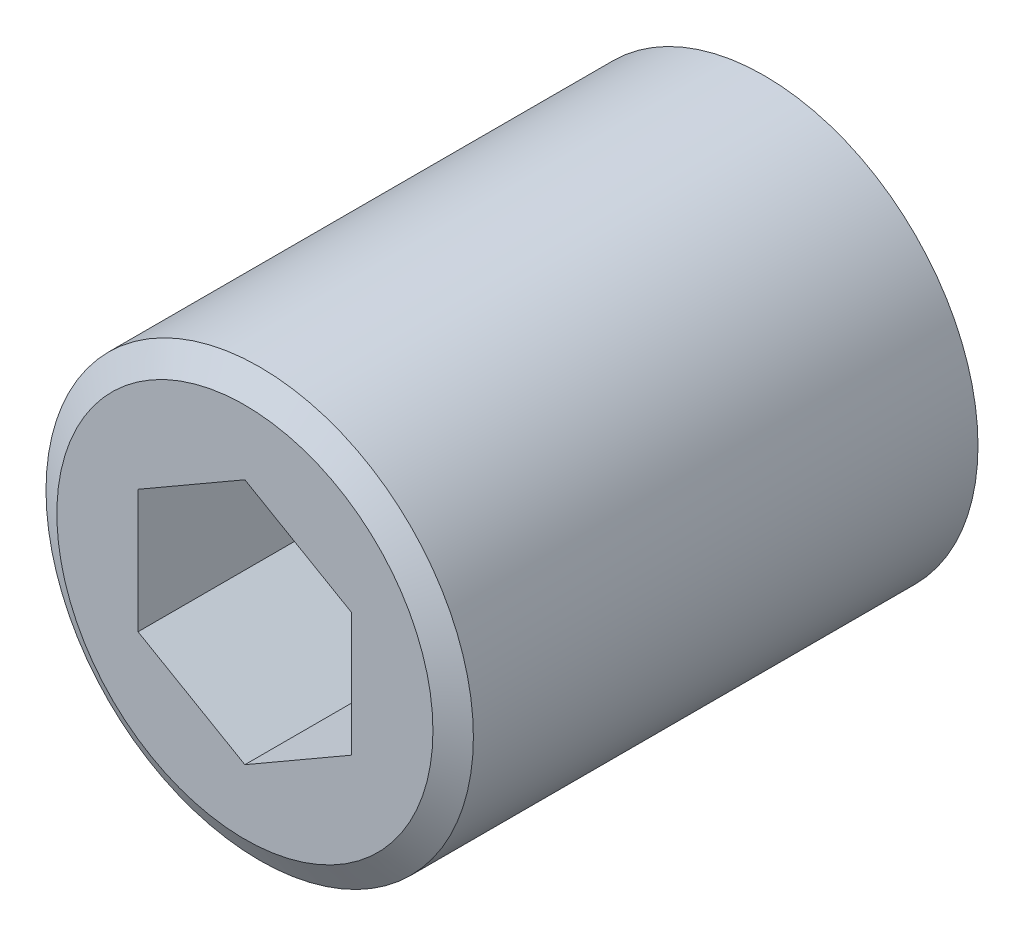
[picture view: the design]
ISO-10303-21;
HEADER;
FILE_DESCRIPTION(('STEP AP214'),'2;1');
FILE_NAME('part.step','',(''),(''),'','','');
FILE_SCHEMA(('AUTOMOTIVE_DESIGN { 1 0 10303 214 1 1 1 1 }'));
ENDSEC;
DATA;
#1=APPLICATION_CONTEXT('core data for automotive mechanical design processes');
#2=APPLICATION_PROTOCOL_DEFINITION('international standard','automotive_design',2000,#1);
#3=PRODUCT_CONTEXT('',#1,'mechanical');
#4=PRODUCT('Part','Part','',(#3));
#5=PRODUCT_RELATED_PRODUCT_CATEGORY('part','',(#4));
#6=PRODUCT_DEFINITION_FORMATION('','',#4);
#7=PRODUCT_DEFINITION_CONTEXT('part definition',#1,'design');
#8=PRODUCT_DEFINITION('design','',#6,#7);
#9=PRODUCT_DEFINITION_SHAPE('','',#8);
#10=(LENGTH_UNIT() NAMED_UNIT(*) SI_UNIT(.MILLI.,.METRE.));
#11=(NAMED_UNIT(*) PLANE_ANGLE_UNIT() SI_UNIT($,.RADIAN.));
#12=(NAMED_UNIT(*) SI_UNIT($,.STERADIAN.) SOLID_ANGLE_UNIT());
#13=UNCERTAINTY_MEASURE_WITH_UNIT(LENGTH_MEASURE(1.E-05),#10,'distance_accuracy_value','');
#14=(GEOMETRIC_REPRESENTATION_CONTEXT(3) GLOBAL_UNCERTAINTY_ASSIGNED_CONTEXT((#13)) GLOBAL_UNIT_ASSIGNED_CONTEXT((#10,
#11,#12)) REPRESENTATION_CONTEXT('',''));
#15=CARTESIAN_POINT('',(0.,0.,0.));
#16=DIRECTION('',(0.,0.,1.));
#17=DIRECTION('',(1.,0.,0.));
#18=AXIS2_PLACEMENT_3D('',#15,#16,#17);
#19=CARTESIAN_POINT('',(1.5,-6.35,0.));
#20=DIRECTION('',(-0.707106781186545,0.,0.70710678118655));
#21=DIRECTION('',(0.70710678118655,0.,0.707106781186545));
#22=AXIS2_PLACEMENT_3D('',#19,#20,#21);
#23=PLANE('',#22);
#24=CARTESIAN_POINT('',(0.,0.,-1.5));
#25=DIRECTION('',(-0.707106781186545,0.,0.70710678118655));
#26=DIRECTION('',(-0.70710678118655,0.,-0.707106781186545));
#27=AXIS2_PLACEMENT_3D('',#24,#25,#26);
#28=ELLIPSE('',#27,8.98025612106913,6.35);
#29=CARTESIAN_POINT('',(2.77,-5.71398284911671,1.27));
#30=VERTEX_POINT('',#29);
#31=CARTESIAN_POINT('',(3.,-5.59665078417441,1.5));
#32=VERTEX_POINT('',#31);
#33=EDGE_CURVE('E535',#30,#32,#28,.T.);
#34=ORIENTED_EDGE('',*,*,#33,.F.);
#35=CARTESIAN_POINT('',(0.,0.,-1.5));
#36=DIRECTION('',(-0.707106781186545,0.,0.70710678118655));
#37=DIRECTION('',(0.70710678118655,0.,0.707106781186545));
#38=AXIS2_PLACEMENT_3D('',#35,#36,#37);
#39=ELLIPSE('',#38,8.98025612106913,6.35);
#40=CARTESIAN_POINT('',(2.73216847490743,-5.73216847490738,1.2321684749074));
#41=VERTEX_POINT('',#40);
#42=EDGE_CURVE('E947',#41,#30,#39,.T.);
#43=ORIENTED_EDGE('',*,*,#42,.F.);
#44=DIRECTION('',(-0.577350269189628,0.577350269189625,-0.577350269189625));
#45=VECTOR('',#44,1.);
#46=CARTESIAN_POINT('',(2.11666666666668,-5.11666666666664,0.616666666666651));
#47=LINE('',#46,#45);
#48=CARTESIAN_POINT('',(1.49999999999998,-4.5,0.));
#49=VERTEX_POINT('',#48);
#50=EDGE_CURVE('E684',#41,#49,#47,.T.);
#51=ORIENTED_EDGE('',*,*,#50,.T.);
#52=DIRECTION('',(0.577350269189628,0.577350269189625,0.577350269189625));
#53=VECTOR('',#52,1.);
#54=CARTESIAN_POINT('',(0.883333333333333,-5.11666666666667,-0.616666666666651));
#55=LINE('',#54,#53);
#56=CARTESIAN_POINT('',(3.,-3.,1.5));
#57=VERTEX_POINT('',#56);
#58=EDGE_CURVE('E707',#49,#57,#55,.T.);
#59=ORIENTED_EDGE('',*,*,#58,.T.);
#60=DIRECTION('',(0.,1.,0.));
#61=VECTOR('',#60,1.);
#62=CARTESIAN_POINT('',(3.,-6.35,1.5));
#63=LINE('',#62,#61);
#64=EDGE_CURVE('E911',#32,#57,#63,.T.);
#65=ORIENTED_EDGE('',*,*,#64,.F.);
#66=EDGE_LOOP('',(#34,#43,#51,#59,#65));
#67=FACE_BOUND('',#66,.T.);
#68=ADVANCED_FACE('F15',(#67),#23,.F.);
#69=CARTESIAN_POINT('',(1.5,-6.35,0.));
#70=DIRECTION('',(0.707106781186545,0.,0.70710678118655));
#71=DIRECTION('',(0.70710678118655,0.,-0.707106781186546));
#72=AXIS2_PLACEMENT_3D('',#69,#70,#71);
#73=PLANE('',#72);
#74=CARTESIAN_POINT('',(0.,0.,1.5));
#75=DIRECTION('',(0.707106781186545,0.,0.70710678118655));
#76=DIRECTION('',(0.70710678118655,0.,-0.707106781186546));
#77=AXIS2_PLACEMENT_3D('',#74,#75,#76);
#78=ELLIPSE('',#77,8.98025612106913,6.35);
#79=CARTESIAN_POINT('',(0.,-6.35,1.5));
#80=VERTEX_POINT('',#79);
#81=CARTESIAN_POINT('',(0.229999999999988,-6.34583327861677,1.27));
#82=VERTEX_POINT('',#81);
#83=EDGE_CURVE('E579',#80,#82,#78,.T.);
#84=ORIENTED_EDGE('',*,*,#83,.F.);
#85=DIRECTION('',(0.,1.,0.));
#86=VECTOR('',#85,1.);
#87=CARTESIAN_POINT('',(0.,-6.35,1.5));
#88=LINE('',#87,#86);
#89=CARTESIAN_POINT('',(0.,-6.,1.5));
#90=VERTEX_POINT('',#89);
#91=EDGE_CURVE('E891',#80,#90,#88,.T.);
#92=ORIENTED_EDGE('',*,*,#91,.T.);
#93=DIRECTION('',(0.577350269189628,-0.577350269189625,-0.577350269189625));
#94=VECTOR('',#93,1.);
#95=CARTESIAN_POINT('',(1.11666666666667,-7.11666666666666,0.38333333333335));
#96=LINE('',#95,#94);
#97=CARTESIAN_POINT('',(0.340845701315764,-6.34084570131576,1.1591542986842));
#98=VERTEX_POINT('',#97);
#99=EDGE_CURVE('E671',#90,#98,#96,.T.);
#100=ORIENTED_EDGE('',*,*,#99,.T.);
#101=CARTESIAN_POINT('',(0.,0.,1.5));
#102=DIRECTION('',(0.707106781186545,0.,0.70710678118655));
#103=DIRECTION('',(-0.70710678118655,0.,0.707106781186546));
#104=AXIS2_PLACEMENT_3D('',#101,#102,#103);
#105=ELLIPSE('',#104,8.98025612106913,6.35);
#106=EDGE_CURVE('E946',#82,#98,#105,.T.);
#107=ORIENTED_EDGE('',*,*,#106,.F.);
#108=EDGE_LOOP('',(#84,#92,#100,#107));
#109=FACE_BOUND('',#108,.T.);
#110=ADVANCED_FACE('F1126',(#109),#73,.F.);
#111=CARTESIAN_POINT('',(0.,0.,1.5));
#112=DIRECTION('',(0.707106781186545,0.,0.70710678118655));
#113=DIRECTION('',(0.70710678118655,0.,-0.707106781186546));
#114=AXIS2_PLACEMENT_3D('',#111,#112,#113);
#115=ELLIPSE('',#114,8.98025612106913,6.35);
#116=CARTESIAN_POINT('',(0.229999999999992,6.34583327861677,1.27));
#117=VERTEX_POINT('',#116);
#118=CARTESIAN_POINT('',(0.,6.35,1.5));
#119=VERTEX_POINT('',#118);
#120=EDGE_CURVE('E575',#117,#119,#115,.T.);
#121=ORIENTED_EDGE('',*,*,#120,.F.);
#122=CARTESIAN_POINT('',(0.340845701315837,6.34084570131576,1.15915429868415));
#123=VERTEX_POINT('',#122);
#124=EDGE_CURVE('E391',#123,#117,#105,.T.);
#125=ORIENTED_EDGE('',*,*,#124,.F.);
#126=DIRECTION('',(-0.577350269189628,-0.577350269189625,0.577350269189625));
#127=VECTOR('',#126,1.);
#128=CARTESIAN_POINT('',(-3.11666666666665,2.88333333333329,4.6166666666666));
#129=LINE('',#128,#127);
#130=CARTESIAN_POINT('',(0.,6.,1.5));
#131=VERTEX_POINT('',#130);
#132=EDGE_CURVE('E407',#123,#131,#129,.T.);
#133=ORIENTED_EDGE('',*,*,#132,.T.);
#134=EDGE_CURVE('E897',#131,#119,#88,.T.);
#135=ORIENTED_EDGE('',*,*,#134,.T.);
#136=EDGE_LOOP('',(#121,#125,#133,#135));
#137=FACE_BOUND('',#136,.T.);
#138=ADVANCED_FACE('F1134',(#137),#73,.F.);
#139=CARTESIAN_POINT('',(0.,-6.35,1.5));
#140=DIRECTION('',(-0.70710678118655,0.,0.707106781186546));
#141=DIRECTION('',(0.707106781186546,0.,0.70710678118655));
#142=AXIS2_PLACEMENT_3D('',#139,#140,#141);
#143=PLANE('',#142);
#144=CARTESIAN_POINT('',(0.,0.,1.5));
#145=DIRECTION('',(-0.70710678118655,0.,0.707106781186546));
#146=DIRECTION('',(-0.707106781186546,0.,-0.70710678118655));
#147=AXIS2_PLACEMENT_3D('',#144,#145,#146);
#148=ELLIPSE('',#147,8.98025612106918,6.35);
#149=CARTESIAN_POINT('',(-0.229999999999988,-6.34583327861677,1.27));
#150=VERTEX_POINT('',#149);
#151=EDGE_CURVE('E528',#150,#80,#148,.T.);
#152=ORIENTED_EDGE('',*,*,#151,.F.);
#153=CARTESIAN_POINT('',(0.,0.,1.5));
#154=DIRECTION('',(-0.70710678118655,0.,0.707106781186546));
#155=DIRECTION('',(0.707106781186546,0.,0.70710678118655));
#156=AXIS2_PLACEMENT_3D('',#153,#154,#155);
#157=ELLIPSE('',#156,8.98025612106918,6.35);
#158=CARTESIAN_POINT('',(-0.34084570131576,-6.34084570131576,1.1591542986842));
#159=VERTEX_POINT('',#158);
#160=EDGE_CURVE('E939',#159,#150,#157,.T.);
#161=ORIENTED_EDGE('',*,*,#160,.F.);
#162=DIRECTION('',(0.577350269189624,0.577350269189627,0.577350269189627));
#163=VECTOR('',#162,1.);
#164=CARTESIAN_POINT('',(-0.116666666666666,-6.11666666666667,1.3833333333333));
#165=LINE('',#164,#163);
#166=EDGE_CURVE('E675',#159,#90,#165,.T.);
#167=ORIENTED_EDGE('',*,*,#166,.T.);
#168=ORIENTED_EDGE('',*,*,#91,.F.);
#169=EDGE_LOOP('',(#152,#161,#167,#168));
#170=FACE_BOUND('',#169,.T.);
#171=ADVANCED_FACE('F1395',(#170),#143,.F.);
#172=CARTESIAN_POINT('',(0.,0.,1.5));
#173=DIRECTION('',(-0.70710678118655,0.,0.707106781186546));
#174=DIRECTION('',(-0.707106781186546,0.,-0.70710678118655));
#175=AXIS2_PLACEMENT_3D('',#172,#173,#174);
#176=ELLIPSE('',#175,8.98025612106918,6.35);
#177=CARTESIAN_POINT('',(-0.229999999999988,6.34583327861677,1.27));
#178=VERTEX_POINT('',#177);
#179=EDGE_CURVE('E524',#119,#178,#176,.T.);
#180=ORIENTED_EDGE('',*,*,#179,.F.);
#181=ORIENTED_EDGE('',*,*,#134,.F.);
#182=DIRECTION('',(-0.577350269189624,0.577350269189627,-0.577350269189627));
#183=VECTOR('',#182,1.);
#184=CARTESIAN_POINT('',(4.11666666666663,1.88333333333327,5.61666666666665));
#185=LINE('',#184,#183);
#186=CARTESIAN_POINT('',(-0.340845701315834,6.34084570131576,1.15915429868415));
#187=VERTEX_POINT('',#186);
#188=EDGE_CURVE('E659',#131,#187,#185,.T.);
#189=ORIENTED_EDGE('',*,*,#188,.T.);
#190=EDGE_CURVE('E943',#178,#187,#157,.T.);
#191=ORIENTED_EDGE('',*,*,#190,.F.);
#192=EDGE_LOOP('',(#180,#181,#189,#191));
#193=FACE_BOUND('',#192,.T.);
#194=ADVANCED_FACE('F1392',(#193),#143,.F.);
#195=CARTESIAN_POINT('',(-1.5,-6.35,0.));
#196=DIRECTION('',(0.707106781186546,0.,0.707106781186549));
#197=DIRECTION('',(0.707106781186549,0.,-0.707106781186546));
#198=AXIS2_PLACEMENT_3D('',#195,#196,#197);
#199=PLANE('',#198);
#200=CARTESIAN_POINT('',(0.,0.,-1.5));
#201=DIRECTION('',(0.707106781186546,0.,0.707106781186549));
#202=DIRECTION('',(0.707106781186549,0.,-0.707106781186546));
#203=AXIS2_PLACEMENT_3D('',#200,#201,#202);
#204=ELLIPSE('',#203,8.98025612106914,6.35);
#205=CARTESIAN_POINT('',(-3.,-5.59665078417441,1.5));
#206=VERTEX_POINT('',#205);
#207=CARTESIAN_POINT('',(-2.77,-5.71398284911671,1.27));
#208=VERTEX_POINT('',#207);
#209=EDGE_CURVE('E31',#206,#208,#204,.T.);
#210=ORIENTED_EDGE('',*,*,#209,.F.);
#211=DIRECTION('',(0.,1.,0.));
#212=VECTOR('',#211,1.);
#213=CARTESIAN_POINT('',(-3.,-6.35,1.5));
#214=LINE('',#213,#212);
#215=CARTESIAN_POINT('',(-3.,-3.,1.5));
#216=VERTEX_POINT('',#215);
#217=EDGE_CURVE('E898',#206,#216,#214,.T.);
#218=ORIENTED_EDGE('',*,*,#217,.T.);
#219=DIRECTION('',(0.577350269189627,-0.577350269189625,-0.577350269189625));
#220=VECTOR('',#219,1.);
#221=CARTESIAN_POINT('',(-0.883333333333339,-5.11666666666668,-0.616666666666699));
#222=LINE('',#221,#220);
#223=CARTESIAN_POINT('',(-1.5,-4.49999999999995,0.));
#224=VERTEX_POINT('',#223);
#225=EDGE_CURVE('E723',#216,#224,#222,.T.);
#226=ORIENTED_EDGE('',*,*,#225,.T.);
#227=DIRECTION('',(-0.577350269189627,-0.577350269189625,0.577350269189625));
#228=VECTOR('',#227,1.);
#229=CARTESIAN_POINT('',(-2.11666666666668,-5.11666666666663,0.616666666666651));
#230=LINE('',#229,#228);
#231=CARTESIAN_POINT('',(-2.73216847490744,-5.73216847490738,1.2321684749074));
#232=VERTEX_POINT('',#231);
#233=EDGE_CURVE('E699',#224,#232,#230,.T.);
#234=ORIENTED_EDGE('',*,*,#233,.T.);
#235=CARTESIAN_POINT('',(0.,0.,-1.5));
#236=DIRECTION('',(0.707106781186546,0.,0.707106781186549));
#237=DIRECTION('',(-0.707106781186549,0.,0.707106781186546));
#238=AXIS2_PLACEMENT_3D('',#235,#236,#237);
#239=ELLIPSE('',#238,8.98025612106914,6.35);
#240=EDGE_CURVE('E938',#208,#232,#239,.T.);
#241=ORIENTED_EDGE('',*,*,#240,.F.);
#242=EDGE_LOOP('',(#210,#218,#226,#234,#241));
#243=FACE_BOUND('',#242,.T.);
#244=ADVANCED_FACE('F1714',(#243),#199,.F.);
#245=CARTESIAN_POINT('',(-3.,-6.35,1.5));
#246=DIRECTION('',(-0.707106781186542,0.,0.707106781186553));
#247=DIRECTION('',(0.707106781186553,0.,0.707106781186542));
#248=AXIS2_PLACEMENT_3D('',#245,#246,#247);
#249=PLANE('',#248);
#250=CARTESIAN_POINT('',(0.,0.,4.5));
#251=DIRECTION('',(-0.707106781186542,0.,0.707106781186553));
#252=DIRECTION('',(-0.707106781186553,0.,-0.707106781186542));
#253=AXIS2_PLACEMENT_3D('',#250,#251,#252);
#254=ELLIPSE('',#253,8.98025612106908,6.35);
#255=CARTESIAN_POINT('',(-3.23,-5.46713819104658,1.27));
#256=VERTEX_POINT('',#255);
#257=EDGE_CURVE('E569',#256,#206,#254,.T.);
#258=ORIENTED_EDGE('',*,*,#257,.F.);
#259=CARTESIAN_POINT('',(0.,0.,4.5));
#260=DIRECTION('',(-0.707106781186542,0.,0.707106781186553));
#261=DIRECTION('',(0.707106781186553,0.,0.707106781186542));
#262=AXIS2_PLACEMENT_3D('',#259,#260,#261);
#263=ELLIPSE('',#262,8.98025612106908,6.35);
#264=CARTESIAN_POINT('',(-4.49012806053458,-4.49012806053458,0.00987193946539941));
#265=VERTEX_POINT('',#264);
#266=EDGE_CURVE('E929',#265,#256,#263,.T.);
#267=ORIENTED_EDGE('',*,*,#266,.F.);
#268=DIRECTION('',(0.577350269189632,0.577350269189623,0.577350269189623));
#269=VECTOR('',#268,1.);
#270=CARTESIAN_POINT('',(-4.11666666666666,-4.11666666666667,0.38333333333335));
#271=LINE('',#270,#269);
#272=EDGE_CURVE('E726',#265,#216,#271,.T.);
#273=ORIENTED_EDGE('',*,*,#272,.T.);
#274=ORIENTED_EDGE('',*,*,#217,.F.);
#275=EDGE_LOOP('',(#258,#267,#273,#274));
#276=FACE_BOUND('',#275,.T.);
#277=ADVANCED_FACE('F1706',(#276),#249,.F.);
#278=CARTESIAN_POINT('',(-4.5,-6.35,0.));
#279=DIRECTION('',(0.707106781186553,0.,0.707106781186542));
#280=DIRECTION('',(0.707106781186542,0.,-0.707106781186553));
#281=AXIS2_PLACEMENT_3D('',#278,#279,#280);
#282=PLANE('',#281);
#283=CARTESIAN_POINT('',(0.,0.,-4.5));
#284=DIRECTION('',(0.707106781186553,0.,0.707106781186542));
#285=DIRECTION('',(0.707106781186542,0.,-0.707106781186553));
#286=AXIS2_PLACEMENT_3D('',#283,#284,#285);
#287=ELLIPSE('',#286,8.98025612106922,6.35);
#288=CARTESIAN_POINT('',(-5.77,2.65133928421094,1.27));
#289=VERTEX_POINT('',#288);
#290=CARTESIAN_POINT('',(-6.,2.07906228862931,1.5));
#291=VERTEX_POINT('',#290);
#292=EDGE_CURVE('E565',#289,#291,#287,.T.);
#293=ORIENTED_EDGE('',*,*,#292,.F.);
#294=CARTESIAN_POINT('',(0.,0.,-4.5));
#295=DIRECTION('',(0.707106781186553,0.,0.707106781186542));
#296=DIRECTION('',(-0.707106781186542,0.,0.707106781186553));
#297=AXIS2_PLACEMENT_3D('',#294,#295,#296);
#298=ELLIPSE('',#297,8.98025612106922,6.35);
#299=CARTESIAN_POINT('',(-5.73216847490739,2.73216847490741,1.2321684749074));
#300=VERTEX_POINT('',#299);
#301=EDGE_CURVE('E924',#300,#289,#298,.T.);
#302=ORIENTED_EDGE('',*,*,#301,.F.);
#303=DIRECTION('',(0.57735026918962,-0.577350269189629,-0.577350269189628));
#304=VECTOR('',#303,1.);
#305=CARTESIAN_POINT('',(-1.88333333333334,-1.1166666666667,-2.6166666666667));
#306=LINE('',#305,#304);
#307=CARTESIAN_POINT('',(-4.5,1.49999999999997,0.));
#308=VERTEX_POINT('',#307);
#309=EDGE_CURVE('E883',#300,#308,#306,.T.);
#310=ORIENTED_EDGE('',*,*,#309,.T.);
#311=DIRECTION('',(-0.57735026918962,-0.577350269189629,0.577350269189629));
#312=VECTOR('',#311,1.);
#313=CARTESIAN_POINT('',(-7.11666666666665,-1.11666666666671,2.6166666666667));
#314=LINE('',#313,#312);
#315=CARTESIAN_POINT('',(-6.,0.,1.5));
#316=VERTEX_POINT('',#315);
#317=EDGE_CURVE('E844',#308,#316,#314,.T.);
#318=ORIENTED_EDGE('',*,*,#317,.T.);
#319=DIRECTION('',(0.,1.,0.));
#320=VECTOR('',#319,1.);
#321=CARTESIAN_POINT('',(-6.,-6.35,1.5));
#322=LINE('',#321,#320);
#323=EDGE_CURVE('E906',#316,#291,#322,.T.);
#324=ORIENTED_EDGE('',*,*,#323,.T.);
#325=EDGE_LOOP('',(#293,#302,#310,#318,#324));
#326=FACE_BOUND('',#325,.T.);
#327=ADVANCED_FACE('F2388',(#326),#282,.F.);
#328=CARTESIAN_POINT('',(0.,0.,-4.5));
#329=DIRECTION('',(0.707106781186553,0.,0.707106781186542));
#330=DIRECTION('',(0.707106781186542,0.,-0.707106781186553));
#331=AXIS2_PLACEMENT_3D('',#328,#329,#330);
#332=ELLIPSE('',#331,8.98025612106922,6.35);
#333=CARTESIAN_POINT('',(-6.,-2.07906228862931,1.5));
#334=VERTEX_POINT('',#333);
#335=CARTESIAN_POINT('',(-5.77,-2.65133928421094,1.27));
#336=VERTEX_POINT('',#335);
#337=EDGE_CURVE('E559',#334,#336,#332,.T.);
#338=ORIENTED_EDGE('',*,*,#337,.F.);
#339=EDGE_CURVE('E903',#334,#316,#322,.T.);
#340=ORIENTED_EDGE('',*,*,#339,.T.);
#341=DIRECTION('',(0.57735026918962,-0.577350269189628,-0.577350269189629));
#342=VECTOR('',#341,1.);
#343=CARTESIAN_POINT('',(-2.88333333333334,-3.11666666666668,-1.6166666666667));
#344=LINE('',#343,#342);
#345=CARTESIAN_POINT('',(-4.5,-1.5,0.));
#346=VERTEX_POINT('',#345);
#347=EDGE_CURVE('E801',#316,#346,#344,.T.);
#348=ORIENTED_EDGE('',*,*,#347,.T.);
#349=DIRECTION('',(-0.57735026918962,-0.577350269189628,0.577350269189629));
#350=VECTOR('',#349,1.);
#351=CARTESIAN_POINT('',(-6.11666666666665,-3.11666666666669,1.61666666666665));
#352=LINE('',#351,#350);
#353=CARTESIAN_POINT('',(-5.73216847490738,-2.73216847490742,1.2321684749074));
#354=VERTEX_POINT('',#353);
#355=EDGE_CURVE('E762',#346,#354,#352,.T.);
#356=ORIENTED_EDGE('',*,*,#355,.T.);
#357=EDGE_CURVE('E928',#336,#354,#298,.T.);
#358=ORIENTED_EDGE('',*,*,#357,.F.);
#359=EDGE_LOOP('',(#338,#340,#348,#356,#358));
#360=FACE_BOUND('',#359,.T.);
#361=ADVANCED_FACE('F2036',(#360),#282,.F.);
#362=CARTESIAN_POINT('',(-6.,-6.35,1.5));
#363=DIRECTION('',(-0.707106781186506,0.,0.70710678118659));
#364=DIRECTION('',(0.70710678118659,0.,0.707106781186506));
#365=AXIS2_PLACEMENT_3D('',#362,#363,#364);
#366=PLANE('',#365);
#367=CARTESIAN_POINT('',(0.,0.,7.4999999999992));
#368=DIRECTION('',(-0.707106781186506,0.,0.70710678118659));
#369=DIRECTION('',(-0.70710678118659,0.,-0.707106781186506));
#370=AXIS2_PLACEMENT_3D('',#367,#368,#369);
#371=ELLIPSE('',#370,8.98025612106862,6.35);
#372=CARTESIAN_POINT('',(-6.23,1.22865780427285,1.27));
#373=VERTEX_POINT('',#372);
#374=EDGE_CURVE('E39',#291,#373,#371,.T.);
#375=ORIENTED_EDGE('',*,*,#374,.F.);
#376=ORIENTED_EDGE('',*,*,#323,.F.);
#377=DIRECTION('',(-0.577350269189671,0.577350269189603,-0.577350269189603));
#378=VECTOR('',#377,1.);
#379=CARTESIAN_POINT('',(-3.8833333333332,-2.11666666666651,3.61666666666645));
#380=LINE('',#379,#378);
#381=CARTESIAN_POINT('',(-6.34084570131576,0.340845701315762,1.1591542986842));
#382=VERTEX_POINT('',#381);
#383=EDGE_CURVE('E848',#316,#382,#380,.T.);
#384=ORIENTED_EDGE('',*,*,#383,.T.);
#385=CARTESIAN_POINT('',(0.,0.,7.4999999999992));
#386=DIRECTION('',(-0.707106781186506,0.,0.70710678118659));
#387=DIRECTION('',(0.70710678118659,0.,0.707106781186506));
#388=AXIS2_PLACEMENT_3D('',#385,#386,#387);
#389=ELLIPSE('',#388,8.98025612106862,6.35);
#390=EDGE_CURVE('E1031',#373,#382,#389,.T.);
#391=ORIENTED_EDGE('',*,*,#390,.F.);
#392=EDGE_LOOP('',(#375,#376,#384,#391));
#393=FACE_BOUND('',#392,.T.);
#394=ADVANCED_FACE('F2372',(#393),#366,.F.);
#395=CARTESIAN_POINT('',(0.,0.,7.4999999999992));
#396=DIRECTION('',(-0.707106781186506,0.,0.70710678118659));
#397=DIRECTION('',(-0.70710678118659,0.,-0.707106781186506));
#398=AXIS2_PLACEMENT_3D('',#395,#396,#397);
#399=ELLIPSE('',#398,8.98025612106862,6.35);
#400=CARTESIAN_POINT('',(-6.23,-1.22865780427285,1.27));
#401=VERTEX_POINT('',#400);
#402=EDGE_CURVE('E555',#401,#334,#399,.T.);
#403=ORIENTED_EDGE('',*,*,#402,.F.);
#404=CARTESIAN_POINT('',(-6.34084570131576,-0.340845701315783,1.1591542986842));
#405=VERTEX_POINT('',#404);
#406=EDGE_CURVE('E1029',#405,#401,#389,.T.);
#407=ORIENTED_EDGE('',*,*,#406,.F.);
#408=DIRECTION('',(0.577350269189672,0.577350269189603,0.577350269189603));
#409=VECTOR('',#408,1.);
#410=CARTESIAN_POINT('',(-8.1166666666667,-2.11666666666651,-0.616666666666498));
#411=LINE('',#410,#409);
#412=EDGE_CURVE('E804',#405,#316,#411,.T.);
#413=ORIENTED_EDGE('',*,*,#412,.T.);
#414=ORIENTED_EDGE('',*,*,#339,.F.);
#415=EDGE_LOOP('',(#403,#407,#413,#414));
#416=FACE_BOUND('',#415,.T.);
#417=ADVANCED_FACE('F2364',(#416),#366,.F.);
#418=CARTESIAN_POINT('',(6.,-6.35,1.5));
#419=DIRECTION('',(0.707106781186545,0.,0.70710678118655));
#420=DIRECTION('',(0.70710678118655,0.,-0.707106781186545));
#421=AXIS2_PLACEMENT_3D('',#418,#419,#420);
#422=PLANE('',#421);
#423=CARTESIAN_POINT('',(0.,0.,7.5));
#424=DIRECTION('',(0.707106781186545,0.,0.70710678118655));
#425=DIRECTION('',(0.70710678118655,0.,-0.707106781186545));
#426=AXIS2_PLACEMENT_3D('',#423,#424,#425);
#427=ELLIPSE('',#426,8.98025612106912,6.35);
#428=CARTESIAN_POINT('',(6.23,1.22865780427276,1.27));
#429=VERTEX_POINT('',#428);
#430=CARTESIAN_POINT('',(6.,2.07906228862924,1.5));
#431=VERTEX_POINT('',#430);
#432=EDGE_CURVE('E551',#429,#431,#427,.T.);
#433=ORIENTED_EDGE('',*,*,#432,.F.);
#434=CARTESIAN_POINT('',(0.,0.,7.5));
#435=DIRECTION('',(0.707106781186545,0.,0.70710678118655));
#436=DIRECTION('',(-0.70710678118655,0.,0.707106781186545));
#437=AXIS2_PLACEMENT_3D('',#434,#435,#436);
#438=ELLIPSE('',#437,8.98025612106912,6.35);
#439=CARTESIAN_POINT('',(6.34084570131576,0.340845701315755,1.1591542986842));
#440=VERTEX_POINT('',#439);
#441=EDGE_CURVE('E1030',#440,#429,#438,.T.);
#442=ORIENTED_EDGE('',*,*,#441,.F.);
#443=DIRECTION('',(-0.577350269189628,-0.577350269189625,0.577350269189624));
#444=VECTOR('',#443,1.);
#445=CARTESIAN_POINT('',(3.88333333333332,-2.11666666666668,3.61666666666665));
#446=LINE('',#445,#444);
#447=CARTESIAN_POINT('',(6.,0.,1.5));
#448=VERTEX_POINT('',#447);
#449=EDGE_CURVE('E816',#440,#448,#446,.T.);
#450=ORIENTED_EDGE('',*,*,#449,.T.);
#451=DIRECTION('',(0.,1.,0.));
#452=VECTOR('',#451,1.);
#453=CARTESIAN_POINT('',(6.,-6.35,1.5));
#454=LINE('',#453,#452);
#455=EDGE_CURVE('E910',#448,#431,#454,.T.);
#456=ORIENTED_EDGE('',*,*,#455,.T.);
#457=EDGE_LOOP('',(#433,#442,#450,#456));
#458=FACE_BOUND('',#457,.T.);
#459=ADVANCED_FACE('F2062',(#458),#422,.F.);
#460=CARTESIAN_POINT('',(0.,0.,7.5));
#461=DIRECTION('',(0.707106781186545,0.,0.70710678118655));
#462=DIRECTION('',(0.70710678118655,0.,-0.707106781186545));
#463=AXIS2_PLACEMENT_3D('',#460,#461,#462);
#464=ELLIPSE('',#463,8.98025612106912,6.35);
#465=CARTESIAN_POINT('',(6.,-2.07906228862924,1.5));
#466=VERTEX_POINT('',#465);
#467=CARTESIAN_POINT('',(6.23,-1.22865780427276,1.27));
#468=VERTEX_POINT('',#467);
#469=EDGE_CURVE('E543',#466,#468,#464,.T.);
#470=ORIENTED_EDGE('',*,*,#469,.F.);
#471=EDGE_CURVE('E907',#466,#448,#454,.T.);
#472=ORIENTED_EDGE('',*,*,#471,.T.);
#473=DIRECTION('',(0.577350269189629,-0.577350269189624,-0.577350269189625));
#474=VECTOR('',#473,1.);
#475=CARTESIAN_POINT('',(8.11666666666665,-2.11666666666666,-0.616666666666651));
#476=LINE('',#475,#474);
#477=CARTESIAN_POINT('',(6.34084570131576,-0.340845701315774,1.1591542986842));
#478=VERTEX_POINT('',#477);
#479=EDGE_CURVE('E774',#448,#478,#476,.T.);
#480=ORIENTED_EDGE('',*,*,#479,.T.);
#481=EDGE_CURVE('E1025',#468,#478,#438,.T.);
#482=ORIENTED_EDGE('',*,*,#481,.F.);
#483=EDGE_LOOP('',(#470,#472,#480,#482));
#484=FACE_BOUND('',#483,.T.);
#485=ADVANCED_FACE('F2076',(#484),#422,.F.);
#486=CARTESIAN_POINT('',(4.5,-6.35,0.));
#487=DIRECTION('',(-0.70710678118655,0.,0.707106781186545));
#488=DIRECTION('',(0.707106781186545,0.,0.70710678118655));
#489=AXIS2_PLACEMENT_3D('',#486,#487,#488);
#490=PLANE('',#489);
#491=CARTESIAN_POINT('',(0.,0.,-4.5));
#492=DIRECTION('',(-0.70710678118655,0.,0.707106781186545));
#493=DIRECTION('',(-0.707106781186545,0.,-0.70710678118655));
#494=AXIS2_PLACEMENT_3D('',#491,#492,#493);
#495=ELLIPSE('',#494,8.98025612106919,6.35);
#496=CARTESIAN_POINT('',(5.77,2.65133928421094,1.27));
#497=VERTEX_POINT('',#496);
#498=EDGE_CURVE('E547',#431,#497,#495,.T.);
#499=ORIENTED_EDGE('',*,*,#498,.F.);
#500=ORIENTED_EDGE('',*,*,#455,.F.);
#501=DIRECTION('',(-0.577350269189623,0.577350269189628,-0.577350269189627));
#502=VECTOR('',#501,1.);
#503=CARTESIAN_POINT('',(7.11666666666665,-1.1166666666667,2.61666666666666));
#504=LINE('',#503,#502);
#505=CARTESIAN_POINT('',(4.5,1.49999999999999,0.));
#506=VERTEX_POINT('',#505);
#507=EDGE_CURVE('E812',#448,#506,#504,.T.);
#508=ORIENTED_EDGE('',*,*,#507,.T.);
#509=DIRECTION('',(0.577350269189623,0.577350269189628,0.577350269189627));
#510=VECTOR('',#509,1.);
#511=CARTESIAN_POINT('',(1.88333333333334,-1.11666666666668,-2.6166666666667));
#512=LINE('',#511,#510);
#513=CARTESIAN_POINT('',(5.73216847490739,2.73216847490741,1.2321684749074));
#514=VERTEX_POINT('',#513);
#515=EDGE_CURVE('E856',#506,#514,#512,.T.);
#516=ORIENTED_EDGE('',*,*,#515,.T.);
#517=CARTESIAN_POINT('',(0.,0.,-4.5));
#518=DIRECTION('',(-0.70710678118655,0.,0.707106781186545));
#519=DIRECTION('',(0.707106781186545,0.,0.70710678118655));
#520=AXIS2_PLACEMENT_3D('',#517,#518,#519);
#521=ELLIPSE('',#520,8.98025612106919,6.35);
#522=EDGE_CURVE('E923',#497,#514,#521,.T.);
#523=ORIENTED_EDGE('',*,*,#522,.F.);
#524=EDGE_LOOP('',(#499,#500,#508,#516,#523));
#525=FACE_BOUND('',#524,.T.);
#526=ADVANCED_FACE('F2059',(#525),#490,.F.);
#527=CARTESIAN_POINT('',(0.,0.,-4.5));
#528=DIRECTION('',(-0.70710678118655,0.,0.707106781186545));
#529=DIRECTION('',(-0.707106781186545,0.,-0.70710678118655));
#530=AXIS2_PLACEMENT_3D('',#527,#528,#529);
#531=ELLIPSE('',#530,8.98025612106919,6.35);
#532=CARTESIAN_POINT('',(5.77,-2.65133928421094,1.27));
#533=VERTEX_POINT('',#532);
#534=EDGE_CURVE('E539',#533,#466,#531,.T.);
#535=ORIENTED_EDGE('',*,*,#534,.F.);
#536=CARTESIAN_POINT('',(5.73216847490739,-2.73216847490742,1.2321684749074));
#537=VERTEX_POINT('',#536);
#538=EDGE_CURVE('E919',#537,#533,#521,.T.);
#539=ORIENTED_EDGE('',*,*,#538,.F.);
#540=DIRECTION('',(-0.577350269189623,0.577350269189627,-0.577350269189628));
#541=VECTOR('',#540,1.);
#542=CARTESIAN_POINT('',(6.11666666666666,-3.11666666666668,1.61666666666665));
#543=LINE('',#542,#541);
#544=CARTESIAN_POINT('',(4.5,-1.5,0.));
#545=VERTEX_POINT('',#544);
#546=EDGE_CURVE('E734',#537,#545,#543,.T.);
#547=ORIENTED_EDGE('',*,*,#546,.T.);
#548=DIRECTION('',(0.577350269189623,0.577350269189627,0.577350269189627));
#549=VECTOR('',#548,1.);
#550=CARTESIAN_POINT('',(2.88333333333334,-3.11666666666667,-1.6166666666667));
#551=LINE('',#550,#549);
#552=EDGE_CURVE('E770',#545,#448,#551,.T.);
#553=ORIENTED_EDGE('',*,*,#552,.T.);
#554=ORIENTED_EDGE('',*,*,#471,.F.);
#555=EDGE_LOOP('',(#535,#539,#547,#553,#554));
#556=FACE_BOUND('',#555,.T.);
#557=ADVANCED_FACE('F1189',(#556),#490,.F.);
#558=CARTESIAN_POINT('',(3.,-6.35,1.5));
#559=DIRECTION('',(0.707106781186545,0.,0.70710678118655));
#560=DIRECTION('',(0.70710678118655,0.,-0.707106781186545));
#561=AXIS2_PLACEMENT_3D('',#558,#559,#560);
#562=PLANE('',#561);
#563=CARTESIAN_POINT('',(0.,0.,4.5));
#564=DIRECTION('',(0.707106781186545,0.,0.70710678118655));
#565=DIRECTION('',(0.70710678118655,0.,-0.707106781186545));
#566=AXIS2_PLACEMENT_3D('',#563,#564,#565);
#567=ELLIPSE('',#566,8.98025612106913,6.35);
#568=CARTESIAN_POINT('',(3.23,-5.46713819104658,1.27));
#569=VERTEX_POINT('',#568);
#570=EDGE_CURVE('E531',#32,#569,#567,.T.);
#571=ORIENTED_EDGE('',*,*,#570,.F.);
#572=ORIENTED_EDGE('',*,*,#64,.T.);
#573=DIRECTION('',(0.577350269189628,-0.577350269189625,-0.577350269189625));
#574=VECTOR('',#573,1.);
#575=CARTESIAN_POINT('',(4.11666666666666,-4.11666666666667,0.38333333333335));
#576=LINE('',#575,#574);
#577=CARTESIAN_POINT('',(4.49012806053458,-4.49012806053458,0.00987193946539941));
#578=VERTEX_POINT('',#577);
#579=EDGE_CURVE('E1055',#57,#578,#576,.T.);
#580=ORIENTED_EDGE('',*,*,#579,.T.);
#581=CARTESIAN_POINT('',(0.,0.,4.5));
#582=DIRECTION('',(0.707106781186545,0.,0.70710678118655));
#583=DIRECTION('',(-0.70710678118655,0.,0.707106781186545));
#584=AXIS2_PLACEMENT_3D('',#581,#582,#583);
#585=ELLIPSE('',#584,8.98025612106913,6.35);
#586=EDGE_CURVE('E918',#569,#578,#585,.T.);
#587=ORIENTED_EDGE('',*,*,#586,.F.);
#588=EDGE_LOOP('',(#571,#572,#580,#587));
#589=FACE_BOUND('',#588,.T.);
#590=ADVANCED_FACE('F1142',(#589),#562,.F.);
#591=CARTESIAN_POINT('',(0.,0.,-1.5));
#592=DIRECTION('',(-0.707106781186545,0.,0.70710678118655));
#593=DIRECTION('',(-0.70710678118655,0.,-0.707106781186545));
#594=AXIS2_PLACEMENT_3D('',#591,#592,#593);
#595=ELLIPSE('',#594,8.98025612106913,6.35);
#596=CARTESIAN_POINT('',(3.,5.59665078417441,1.5));
#597=VERTEX_POINT('',#596);
#598=CARTESIAN_POINT('',(2.77,5.71398284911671,1.27));
#599=VERTEX_POINT('',#598);
#600=EDGE_CURVE('E512',#597,#599,#595,.T.);
#601=ORIENTED_EDGE('',*,*,#600,.F.);
#602=CARTESIAN_POINT('',(3.,3.,1.5));
#603=VERTEX_POINT('',#602);
#604=EDGE_CURVE('E890',#603,#597,#63,.T.);
#605=ORIENTED_EDGE('',*,*,#604,.F.);
#606=DIRECTION('',(-0.577350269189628,0.577350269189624,-0.577350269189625));
#607=VECTOR('',#606,1.);
#608=CARTESIAN_POINT('',(5.11666666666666,0.883333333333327,3.61666666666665));
#609=LINE('',#608,#607);
#610=CARTESIAN_POINT('',(1.50000000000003,4.5,0.));
#611=VERTEX_POINT('',#610);
#612=EDGE_CURVE('E587',#603,#611,#609,.T.);
#613=ORIENTED_EDGE('',*,*,#612,.T.);
#614=DIRECTION('',(0.577350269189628,0.577350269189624,0.577350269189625));
#615=VECTOR('',#614,1.);
#616=CARTESIAN_POINT('',(-2.11666666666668,0.883333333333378,-3.61666666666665));
#617=LINE('',#616,#615);
#618=CARTESIAN_POINT('',(2.73216847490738,5.73216847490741,1.23216847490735));
#619=VERTEX_POINT('',#618);
#620=EDGE_CURVE('E636',#611,#619,#617,.T.);
#621=ORIENTED_EDGE('',*,*,#620,.T.);
#622=EDGE_CURVE('E951',#599,#619,#39,.T.);
#623=ORIENTED_EDGE('',*,*,#622,.F.);
#624=EDGE_LOOP('',(#601,#605,#613,#621,#623));
#625=FACE_BOUND('',#624,.T.);
#626=ADVANCED_FACE('F1129',(#625),#23,.F.);
#627=CARTESIAN_POINT('',(0.,0.,-1.5));
#628=DIRECTION('',(0.707106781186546,0.,0.707106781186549));
#629=DIRECTION('',(0.707106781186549,0.,-0.707106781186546));
#630=AXIS2_PLACEMENT_3D('',#627,#628,#629);
#631=ELLIPSE('',#630,8.98025612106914,6.35);
#632=CARTESIAN_POINT('',(-2.77,5.71398284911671,1.27));
#633=VERTEX_POINT('',#632);
#634=CARTESIAN_POINT('',(-3.,5.59665078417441,1.5));
#635=VERTEX_POINT('',#634);
#636=EDGE_CURVE('E520',#633,#635,#631,.T.);
#637=ORIENTED_EDGE('',*,*,#636,.F.);
#638=CARTESIAN_POINT('',(-2.73216847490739,5.7321684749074,1.23216847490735));
#639=VERTEX_POINT('',#638);
#640=EDGE_CURVE('E934',#639,#633,#239,.T.);
#641=ORIENTED_EDGE('',*,*,#640,.F.);
#642=DIRECTION('',(0.577350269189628,-0.577350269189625,-0.577350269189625));
#643=VECTOR('',#642,1.);
#644=CARTESIAN_POINT('',(2.11666666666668,0.883333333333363,-3.6166666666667));
#645=LINE('',#644,#643);
#646=CARTESIAN_POINT('',(-1.5,4.5,0.));
#647=VERTEX_POINT('',#646);
#648=EDGE_CURVE('E651',#639,#647,#645,.T.);
#649=ORIENTED_EDGE('',*,*,#648,.T.);
#650=DIRECTION('',(-0.577350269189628,-0.577350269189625,0.577350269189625));
#651=VECTOR('',#650,1.);
#652=CARTESIAN_POINT('',(-5.11666666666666,0.883333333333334,3.61666666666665));
#653=LINE('',#652,#651);
#654=CARTESIAN_POINT('',(-3.,3.,1.5));
#655=VERTEX_POINT('',#654);
#656=EDGE_CURVE('E623',#647,#655,#653,.T.);
#657=ORIENTED_EDGE('',*,*,#656,.T.);
#658=EDGE_CURVE('E902',#655,#635,#214,.T.);
#659=ORIENTED_EDGE('',*,*,#658,.T.);
#660=EDGE_LOOP('',(#637,#641,#649,#657,#659));
#661=FACE_BOUND('',#660,.T.);
#662=ADVANCED_FACE('F1141',(#661),#199,.F.);
#663=CARTESIAN_POINT('',(0.,0.,4.5));
#664=DIRECTION('',(-0.707106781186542,0.,0.707106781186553));
#665=DIRECTION('',(-0.707106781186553,0.,-0.707106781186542));
#666=AXIS2_PLACEMENT_3D('',#663,#664,#665);
#667=ELLIPSE('',#666,8.98025612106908,6.35);
#668=CARTESIAN_POINT('',(-3.23,5.46713819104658,1.27));
#669=VERTEX_POINT('',#668);
#670=EDGE_CURVE('E516',#635,#669,#667,.T.);
#671=ORIENTED_EDGE('',*,*,#670,.F.);
#672=ORIENTED_EDGE('',*,*,#658,.F.);
#673=DIRECTION('',(-0.577350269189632,0.577350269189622,-0.577350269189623));
#674=VECTOR('',#673,1.);
#675=CARTESIAN_POINT('',(0.116666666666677,-0.116666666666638,4.6166666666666));
#676=LINE('',#675,#674);
#677=CARTESIAN_POINT('',(-4.4901280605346,4.49012806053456,0.00987193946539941));
#678=VERTEX_POINT('',#677);
#679=EDGE_CURVE('E627',#655,#678,#676,.T.);
#680=ORIENTED_EDGE('',*,*,#679,.T.);
#681=EDGE_CURVE('E933',#669,#678,#263,.T.);
#682=ORIENTED_EDGE('',*,*,#681,.F.);
#683=EDGE_LOOP('',(#671,#672,#680,#682));
#684=FACE_BOUND('',#683,.T.);
#685=ADVANCED_FACE('F1524',(#684),#249,.F.);
#686=CARTESIAN_POINT('',(0.,0.,4.5));
#687=DIRECTION('',(0.707106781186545,0.,0.70710678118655));
#688=DIRECTION('',(0.70710678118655,0.,-0.707106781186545));
#689=AXIS2_PLACEMENT_3D('',#686,#687,#688);
#690=ELLIPSE('',#689,8.98025612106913,6.35);
#691=CARTESIAN_POINT('',(3.23,5.46713819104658,1.27));
#692=VERTEX_POINT('',#691);
#693=EDGE_CURVE('E508',#692,#597,#690,.T.);
#694=ORIENTED_EDGE('',*,*,#693,.F.);
#695=CARTESIAN_POINT('',(4.4901280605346,4.49012806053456,0.00987193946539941));
#696=VERTEX_POINT('',#695);
#697=EDGE_CURVE('E895',#696,#692,#585,.T.);
#698=ORIENTED_EDGE('',*,*,#697,.F.);
#699=DIRECTION('',(-0.577350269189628,-0.577350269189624,0.577350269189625));
#700=VECTOR('',#699,1.);
#701=CARTESIAN_POINT('',(-0.116666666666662,-0.116666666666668,4.61666666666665));
#702=LINE('',#701,#700);
#703=EDGE_CURVE('E1035',#696,#603,#702,.T.);
#704=ORIENTED_EDGE('',*,*,#703,.T.);
#705=ORIENTED_EDGE('',*,*,#604,.T.);
#706=EDGE_LOOP('',(#694,#698,#704,#705));
#707=FACE_BOUND('',#706,.T.);
#708=ADVANCED_FACE('F1171',(#707),#562,.F.);
#709=CARTESIAN_POINT('',(6.35,3.,1.5));
#710=DIRECTION('',(0.,0.707106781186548,0.707106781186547));
#711=DIRECTION('',(0.,0.707106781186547,-0.707106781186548));
#712=AXIS2_PLACEMENT_3D('',#709,#710,#711);
#713=PLANE('',#712);
#714=CARTESIAN_POINT('',(0.,0.,4.5));
#715=DIRECTION('',(0.,0.707106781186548,0.707106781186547));
#716=DIRECTION('',(0.,0.707106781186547,-0.707106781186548));
#717=AXIS2_PLACEMENT_3D('',#714,#715,#716);
#718=ELLIPSE('',#717,8.98025612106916,6.35);
#719=CARTESIAN_POINT('',(5.59665078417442,3.,1.5));
#720=VERTEX_POINT('',#719);
#721=CARTESIAN_POINT('',(5.4671381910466,3.22999999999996,1.27));
#722=VERTEX_POINT('',#721);
#723=EDGE_CURVE('E504',#720,#722,#718,.T.);
#724=ORIENTED_EDGE('',*,*,#723,.F.);
#725=DIRECTION('',(-1.,0.,0.));
#726=VECTOR('',#725,1.);
#727=CARTESIAN_POINT('',(6.35,3.,1.5));
#728=LINE('',#727,#726);
#729=EDGE_CURVE('E604',#720,#603,#728,.T.);
#730=ORIENTED_EDGE('',*,*,#729,.T.);
#731=ORIENTED_EDGE('',*,*,#703,.F.);
#732=CARTESIAN_POINT('',(0.,0.,4.5));
#733=DIRECTION('',(0.,0.707106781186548,0.707106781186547));
#734=DIRECTION('',(0.,-0.707106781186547,0.707106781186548));
#735=AXIS2_PLACEMENT_3D('',#732,#733,#734);
#736=ELLIPSE('',#735,8.98025612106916,6.35);
#737=EDGE_CURVE('E611',#722,#696,#736,.T.);
#738=ORIENTED_EDGE('',*,*,#737,.F.);
#739=EDGE_LOOP('',(#724,#730,#731,#738));
#740=FACE_BOUND('',#739,.T.);
#741=ADVANCED_FACE('F1432',(#740),#713,.F.);
#742=CARTESIAN_POINT('',(6.35,1.49999999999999,0.));
#743=DIRECTION('',(0.,-0.707106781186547,0.707106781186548));
#744=DIRECTION('',(0.,0.707106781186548,0.707106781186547));
#745=AXIS2_PLACEMENT_3D('',#742,#743,#744);
#746=PLANE('',#745);
#747=CARTESIAN_POINT('',(0.,0.,-1.5));
#748=DIRECTION('',(0.,-0.707106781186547,0.707106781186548));
#749=DIRECTION('',(0.,-0.707106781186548,-0.707106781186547));
#750=AXIS2_PLACEMENT_3D('',#747,#748,#749);
#751=ELLIPSE('',#750,8.98025612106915,6.35);
#752=CARTESIAN_POINT('',(5.71398284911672,2.77,1.27));
#753=VERTEX_POINT('',#752);
#754=EDGE_CURVE('E500',#753,#720,#751,.T.);
#755=ORIENTED_EDGE('',*,*,#754,.F.);
#756=CARTESIAN_POINT('',(0.,0.,-1.5));
#757=DIRECTION('',(0.,-0.707106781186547,0.707106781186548));
#758=DIRECTION('',(0.,0.707106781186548,0.707106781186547));
#759=AXIS2_PLACEMENT_3D('',#756,#757,#758);
#760=ELLIPSE('',#759,8.98025612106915,6.35);
#761=EDGE_CURVE('E864',#514,#753,#760,.T.);
#762=ORIENTED_EDGE('',*,*,#761,.F.);
#763=ORIENTED_EDGE('',*,*,#515,.F.);
#764=DIRECTION('',(0.577350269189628,-0.577350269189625,-0.577350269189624));
#765=VECTOR('',#764,1.);
#766=CARTESIAN_POINT('',(6.11666666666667,-0.116666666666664,-1.61666666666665));
#767=LINE('',#766,#765);
#768=EDGE_CURVE('E1039',#603,#506,#767,.T.);
#769=ORIENTED_EDGE('',*,*,#768,.F.);
#770=ORIENTED_EDGE('',*,*,#729,.F.);
#771=EDGE_LOOP('',(#755,#762,#763,#769,#770));
#772=FACE_BOUND('',#771,.T.);
#773=ADVANCED_FACE('F1479',(#772),#746,.F.);
#774=CARTESIAN_POINT('',(6.35,-3.,1.5));
#775=DIRECTION('',(0.,-0.707106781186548,0.707106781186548));
#776=DIRECTION('',(0.,0.707106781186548,0.707106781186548));
#777=AXIS2_PLACEMENT_3D('',#774,#775,#776);
#778=PLANE('',#777);
#779=CARTESIAN_POINT('',(0.,0.,4.5));
#780=DIRECTION('',(0.,-0.707106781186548,0.707106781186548));
#781=DIRECTION('',(0.,-0.707106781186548,-0.707106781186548));
#782=AXIS2_PLACEMENT_3D('',#779,#780,#781);
#783=ELLIPSE('',#782,8.98025612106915,6.35);
#784=CARTESIAN_POINT('',(5.46713819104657,-3.23,1.27));
#785=VERTEX_POINT('',#784);
#786=CARTESIAN_POINT('',(5.5966507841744,-3.,1.5));
#787=VERTEX_POINT('',#786);
#788=EDGE_CURVE('E496',#785,#787,#783,.T.);
#789=ORIENTED_EDGE('',*,*,#788,.F.);
#790=CARTESIAN_POINT('',(0.,0.,4.5));
#791=DIRECTION('',(0.,-0.707106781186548,0.707106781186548));
#792=DIRECTION('',(0.,0.707106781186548,0.707106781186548));
#793=AXIS2_PLACEMENT_3D('',#790,#791,#792);
#794=ELLIPSE('',#793,8.98025612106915,6.35);
#795=EDGE_CURVE('E711',#578,#785,#794,.T.);
#796=ORIENTED_EDGE('',*,*,#795,.F.);
#797=ORIENTED_EDGE('',*,*,#579,.F.);
#798=DIRECTION('',(-1.,0.,0.));
#799=VECTOR('',#798,1.);
#800=CARTESIAN_POINT('',(6.35,-3.,1.5));
#801=LINE('',#800,#799);
#802=EDGE_CURVE('E590',#787,#57,#801,.T.);
#803=ORIENTED_EDGE('',*,*,#802,.F.);
#804=EDGE_LOOP('',(#789,#796,#797,#803));
#805=FACE_BOUND('',#804,.T.);
#806=ADVANCED_FACE('F1483',(#805),#778,.F.);
#807=CARTESIAN_POINT('',(6.35,-1.5,0.));
#808=DIRECTION('',(0.,0.707106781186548,0.707106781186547));
#809=DIRECTION('',(0.,0.707106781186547,-0.707106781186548));
#810=AXIS2_PLACEMENT_3D('',#807,#808,#809);
#811=PLANE('',#810);
#812=CARTESIAN_POINT('',(0.,0.,-1.5));
#813=DIRECTION('',(0.,0.707106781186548,0.707106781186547));
#814=DIRECTION('',(0.,0.707106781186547,-0.707106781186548));
#815=AXIS2_PLACEMENT_3D('',#812,#813,#814);
#816=ELLIPSE('',#815,8.98025612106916,6.35);
#817=CARTESIAN_POINT('',(5.71398284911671,-2.77,1.27));
#818=VERTEX_POINT('',#817);
#819=EDGE_CURVE('E492',#787,#818,#816,.T.);
#820=ORIENTED_EDGE('',*,*,#819,.F.);
#821=ORIENTED_EDGE('',*,*,#802,.T.);
#822=DIRECTION('',(-0.577350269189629,-0.577350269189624,0.577350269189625));
#823=VECTOR('',#822,1.);
#824=CARTESIAN_POINT('',(1.88333333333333,-4.11666666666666,2.61666666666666));
#825=LINE('',#824,#823);
#826=EDGE_CURVE('E1051',#545,#57,#825,.T.);
#827=ORIENTED_EDGE('',*,*,#826,.F.);
#828=ORIENTED_EDGE('',*,*,#546,.F.);
#829=CARTESIAN_POINT('',(0.,0.,-1.5));
#830=DIRECTION('',(0.,0.707106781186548,0.707106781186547));
#831=DIRECTION('',(0.,-0.707106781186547,0.707106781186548));
#832=AXIS2_PLACEMENT_3D('',#829,#830,#831);
#833=ELLIPSE('',#832,8.98025612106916,6.35);
#834=EDGE_CURVE('E742',#818,#537,#833,.T.);
#835=ORIENTED_EDGE('',*,*,#834,.F.);
#836=EDGE_LOOP('',(#820,#821,#827,#828,#835));
#837=FACE_BOUND('',#836,.T.);
#838=ADVANCED_FACE('F1181',(#837),#811,.F.);
#839=CARTESIAN_POINT('',(6.35,0.,1.5));
#840=DIRECTION('',(0.,-0.707106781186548,0.707106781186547));
#841=DIRECTION('',(0.,0.707106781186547,0.707106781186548));
#842=AXIS2_PLACEMENT_3D('',#839,#840,#841);
#843=PLANE('',#842);
#844=CARTESIAN_POINT('',(0.,0.,1.5));
#845=DIRECTION('',(0.,-0.707106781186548,0.707106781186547));
#846=DIRECTION('',(0.,-0.707106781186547,-0.707106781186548));
#847=AXIS2_PLACEMENT_3D('',#844,#845,#846);
#848=ELLIPSE('',#847,8.98025612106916,6.35);
#849=CARTESIAN_POINT('',(6.34583327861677,-0.229999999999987,1.27));
#850=VERTEX_POINT('',#849);
#851=CARTESIAN_POINT('',(6.35,0.,1.5));
#852=VERTEX_POINT('',#851);
#853=EDGE_CURVE('E489',#850,#852,#848,.T.);
#854=ORIENTED_EDGE('',*,*,#853,.F.);
#855=CARTESIAN_POINT('',(0.,0.,1.5));
#856=DIRECTION('',(0.,-0.707106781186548,0.707106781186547));
#857=DIRECTION('',(0.,0.707106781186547,0.707106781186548));
#858=AXIS2_PLACEMENT_3D('',#855,#856,#857);
#859=ELLIPSE('',#858,8.98025612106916,6.35);
#860=EDGE_CURVE('E782',#478,#850,#859,.T.);
#861=ORIENTED_EDGE('',*,*,#860,.F.);
#862=ORIENTED_EDGE('',*,*,#479,.F.);
#863=DIRECTION('',(-1.,0.,0.));
#864=VECTOR('',#863,1.);
#865=CARTESIAN_POINT('',(6.35,0.,1.5));
#866=LINE('',#865,#864);
#867=EDGE_CURVE('E583',#852,#448,#866,.T.);
#868=ORIENTED_EDGE('',*,*,#867,.F.);
#869=EDGE_LOOP('',(#854,#861,#862,#868));
#870=FACE_BOUND('',#869,.T.);
#871=ADVANCED_FACE('F1156',(#870),#843,.F.);
#872=CARTESIAN_POINT('',(6.35,1.49999999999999,0.));
#873=DIRECTION('',(0.,0.707106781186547,0.707106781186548));
#874=DIRECTION('',(0.,0.707106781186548,-0.707106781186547));
#875=AXIS2_PLACEMENT_3D('',#872,#873,#874);
#876=PLANE('',#875);
#877=CARTESIAN_POINT('',(0.,0.,1.5));
#878=DIRECTION('',(0.,0.707106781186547,0.707106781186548));
#879=DIRECTION('',(0.,0.707106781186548,-0.707106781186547));
#880=AXIS2_PLACEMENT_3D('',#877,#878,#879);
#881=ELLIPSE('',#880,8.98025612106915,6.35);
#882=CARTESIAN_POINT('',(6.34583327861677,0.229999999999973,1.27));
#883=VERTEX_POINT('',#882);
#884=EDGE_CURVE('E485',#852,#883,#881,.T.);
#885=ORIENTED_EDGE('',*,*,#884,.F.);
#886=ORIENTED_EDGE('',*,*,#867,.T.);
#887=ORIENTED_EDGE('',*,*,#449,.F.);
#888=CARTESIAN_POINT('',(0.,0.,1.5));
#889=DIRECTION('',(0.,0.707106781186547,0.707106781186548));
#890=DIRECTION('',(0.,-0.707106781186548,0.707106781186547));
#891=AXIS2_PLACEMENT_3D('',#888,#889,#890);
#892=ELLIPSE('',#891,8.98025612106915,6.35);
#893=EDGE_CURVE('E824',#883,#440,#892,.T.);
#894=ORIENTED_EDGE('',*,*,#893,.F.);
#895=EDGE_LOOP('',(#885,#886,#887,#894));
#896=FACE_BOUND('',#895,.T.);
#897=ADVANCED_FACE('F1679',(#896),#876,.F.);
#898=CARTESIAN_POINT('',(0.,0.,1.5));
#899=DIRECTION('',(0.,-0.707106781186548,0.707106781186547));
#900=DIRECTION('',(0.,-0.707106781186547,-0.707106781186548));
#901=AXIS2_PLACEMENT_3D('',#898,#899,#900);
#902=ELLIPSE('',#901,8.98025612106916,6.35);
#903=CARTESIAN_POINT('',(-6.35,0.,1.5));
#904=VERTEX_POINT('',#903);
#905=CARTESIAN_POINT('',(-6.34583327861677,-0.229999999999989,1.27));
#906=VERTEX_POINT('',#905);
#907=EDGE_CURVE('E481',#904,#906,#902,.T.);
#908=ORIENTED_EDGE('',*,*,#907,.F.);
#909=EDGE_CURVE('E589',#316,#904,#866,.T.);
#910=ORIENTED_EDGE('',*,*,#909,.F.);
#911=ORIENTED_EDGE('',*,*,#412,.F.);
#912=CARTESIAN_POINT('',(0.,0.,1.5));
#913=DIRECTION('',(0.,-0.707106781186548,0.707106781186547));
#914=DIRECTION('',(0.,0.707106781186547,0.707106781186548));
#915=AXIS2_PLACEMENT_3D('',#912,#913,#914);
#916=ELLIPSE('',#915,8.98025612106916,6.35);
#917=EDGE_CURVE('E808',#906,#405,#916,.T.);
#918=ORIENTED_EDGE('',*,*,#917,.F.);
#919=EDGE_LOOP('',(#908,#910,#911,#918));
#920=FACE_BOUND('',#919,.T.);
#921=ADVANCED_FACE('F1749',(#920),#843,.F.);
#922=CARTESIAN_POINT('',(0.,0.,1.5));
#923=DIRECTION('',(0.,0.707106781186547,0.707106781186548));
#924=DIRECTION('',(0.,0.707106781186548,-0.707106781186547));
#925=AXIS2_PLACEMENT_3D('',#922,#923,#924);
#926=ELLIPSE('',#925,8.98025612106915,6.35);
#927=CARTESIAN_POINT('',(-6.34583327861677,0.229999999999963,1.27));
#928=VERTEX_POINT('',#927);
#929=EDGE_CURVE('E477',#928,#904,#926,.T.);
#930=ORIENTED_EDGE('',*,*,#929,.F.);
#931=CARTESIAN_POINT('',(0.,0.,1.5));
#932=DIRECTION('',(0.,0.707106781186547,0.707106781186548));
#933=DIRECTION('',(0.,-0.707106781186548,0.707106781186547));
#934=AXIS2_PLACEMENT_3D('',#931,#932,#933);
#935=ELLIPSE('',#934,8.98025612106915,6.35);
#936=EDGE_CURVE('E852',#382,#928,#935,.T.);
#937=ORIENTED_EDGE('',*,*,#936,.F.);
#938=ORIENTED_EDGE('',*,*,#383,.F.);
#939=ORIENTED_EDGE('',*,*,#909,.T.);
#940=EDGE_LOOP('',(#930,#937,#938,#939));
#941=FACE_BOUND('',#940,.T.);
#942=ADVANCED_FACE('F1758',(#941),#876,.F.);
#943=CARTESIAN_POINT('',(0.,0.,4.5));
#944=DIRECTION('',(0.,0.707106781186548,0.707106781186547));
#945=DIRECTION('',(0.,0.707106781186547,-0.707106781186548));
#946=AXIS2_PLACEMENT_3D('',#943,#944,#945);
#947=ELLIPSE('',#946,8.98025612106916,6.35);
#948=CARTESIAN_POINT('',(-5.4671381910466,3.22999999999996,1.27));
#949=VERTEX_POINT('',#948);
#950=CARTESIAN_POINT('',(-5.59665078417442,3.,1.5));
#951=VERTEX_POINT('',#950);
#952=EDGE_CURVE('E473',#949,#951,#947,.T.);
#953=ORIENTED_EDGE('',*,*,#952,.F.);
#954=CARTESIAN_POINT('',(0.,0.,4.5));
#955=DIRECTION('',(0.,0.707106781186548,0.707106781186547));
#956=DIRECTION('',(0.,-0.707106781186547,0.707106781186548));
#957=AXIS2_PLACEMENT_3D('',#954,#955,#956);
#958=ELLIPSE('',#957,8.98025612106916,6.35);
#959=EDGE_CURVE('E631',#678,#949,#958,.T.);
#960=ORIENTED_EDGE('',*,*,#959,.F.);
#961=ORIENTED_EDGE('',*,*,#679,.F.);
#962=EDGE_CURVE('E582',#655,#951,#728,.T.);
#963=ORIENTED_EDGE('',*,*,#962,.T.);
#964=EDGE_LOOP('',(#953,#960,#961,#963));
#965=FACE_BOUND('',#964,.T.);
#966=ADVANCED_FACE('F1481',(#965),#713,.F.);
#967=CARTESIAN_POINT('',(0.,0.,-1.5));
#968=DIRECTION('',(0.,-0.707106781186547,0.707106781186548));
#969=DIRECTION('',(0.,-0.707106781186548,-0.707106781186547));
#970=AXIS2_PLACEMENT_3D('',#967,#968,#969);
#971=ELLIPSE('',#970,8.98025612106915,6.35);
#972=CARTESIAN_POINT('',(-5.71398284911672,2.77,1.27));
#973=VERTEX_POINT('',#972);
#974=EDGE_CURVE('E469',#951,#973,#971,.T.);
#975=ORIENTED_EDGE('',*,*,#974,.F.);
#976=ORIENTED_EDGE('',*,*,#962,.F.);
#977=DIRECTION('',(0.577350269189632,0.577350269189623,0.577350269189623));
#978=VECTOR('',#977,1.);
#979=CARTESIAN_POINT('',(-6.11666666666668,-0.116666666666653,-1.61666666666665));
#980=LINE('',#979,#978);
#981=EDGE_CURVE('E879',#308,#655,#980,.T.);
#982=ORIENTED_EDGE('',*,*,#981,.F.);
#983=ORIENTED_EDGE('',*,*,#309,.F.);
#984=CARTESIAN_POINT('',(0.,0.,-1.5));
#985=DIRECTION('',(0.,-0.707106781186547,0.707106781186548));
#986=DIRECTION('',(0.,0.707106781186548,0.707106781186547));
#987=AXIS2_PLACEMENT_3D('',#984,#985,#986);
#988=ELLIPSE('',#987,8.98025612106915,6.35);
#989=EDGE_CURVE('E886',#973,#300,#988,.T.);
#990=ORIENTED_EDGE('',*,*,#989,.F.);
#991=EDGE_LOOP('',(#975,#976,#982,#983,#990));
#992=FACE_BOUND('',#991,.T.);
#993=ADVANCED_FACE('F1485',(#992),#746,.F.);
#994=CARTESIAN_POINT('',(0.,0.,4.5));
#995=DIRECTION('',(0.,-0.707106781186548,0.707106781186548));
#996=DIRECTION('',(0.,-0.707106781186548,-0.707106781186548));
#997=AXIS2_PLACEMENT_3D('',#994,#995,#996);
#998=ELLIPSE('',#997,8.98025612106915,6.35);
#999=CARTESIAN_POINT('',(-5.5966507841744,-3.,1.5));
#1000=VERTEX_POINT('',#999);
#1001=CARTESIAN_POINT('',(-5.46713819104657,-3.23,1.27));
#1002=VERTEX_POINT('',#1001);
#1003=EDGE_CURVE('E465',#1000,#1002,#998,.T.);
#1004=ORIENTED_EDGE('',*,*,#1003,.F.);
#1005=EDGE_CURVE('E595',#216,#1000,#801,.T.);
#1006=ORIENTED_EDGE('',*,*,#1005,.F.);
#1007=ORIENTED_EDGE('',*,*,#272,.F.);
#1008=CARTESIAN_POINT('',(0.,0.,4.5));
#1009=DIRECTION('',(0.,-0.707106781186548,0.707106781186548));
#1010=DIRECTION('',(0.,0.707106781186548,0.707106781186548));
#1011=AXIS2_PLACEMENT_3D('',#1008,#1009,#1010);
#1012=ELLIPSE('',#1011,8.98025612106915,6.35);
#1013=EDGE_CURVE('E730',#1002,#265,#1012,.T.);
#1014=ORIENTED_EDGE('',*,*,#1013,.F.);
#1015=EDGE_LOOP('',(#1004,#1006,#1007,#1014));
#1016=FACE_BOUND('',#1015,.T.);
#1017=ADVANCED_FACE('F1491',(#1016),#778,.F.);
#1018=CARTESIAN_POINT('',(0.,0.,-1.5));
#1019=DIRECTION('',(0.,0.707106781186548,0.707106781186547));
#1020=DIRECTION('',(0.,0.707106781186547,-0.707106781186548));
#1021=AXIS2_PLACEMENT_3D('',#1018,#1019,#1020);
#1022=ELLIPSE('',#1021,8.98025612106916,6.35);
#1023=CARTESIAN_POINT('',(-5.71398284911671,-2.77,1.27));
#1024=VERTEX_POINT('',#1023);
#1025=EDGE_CURVE('E461',#1024,#1000,#1022,.T.);
#1026=ORIENTED_EDGE('',*,*,#1025,.F.);
#1027=CARTESIAN_POINT('',(0.,0.,-1.5));
#1028=DIRECTION('',(0.,0.707106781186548,0.707106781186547));
#1029=DIRECTION('',(0.,-0.707106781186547,0.707106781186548));
#1030=AXIS2_PLACEMENT_3D('',#1027,#1028,#1029);
#1031=ELLIPSE('',#1030,8.98025612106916,6.35);
#1032=EDGE_CURVE('E766',#354,#1024,#1031,.T.);
#1033=ORIENTED_EDGE('',*,*,#1032,.F.);
#1034=ORIENTED_EDGE('',*,*,#355,.F.);
#1035=DIRECTION('',(-0.577350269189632,0.577350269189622,-0.577350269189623));
#1036=VECTOR('',#1035,1.);
#1037=CARTESIAN_POINT('',(-1.88333333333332,-4.11666666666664,2.61666666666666));
#1038=LINE('',#1037,#1036);
#1039=EDGE_CURVE('E758',#216,#346,#1038,.T.);
#1040=ORIENTED_EDGE('',*,*,#1039,.F.);
#1041=ORIENTED_EDGE('',*,*,#1005,.T.);
#1042=EDGE_LOOP('',(#1026,#1033,#1034,#1040,#1041));
#1043=FACE_BOUND('',#1042,.T.);
#1044=ADVANCED_FACE('F1462',(#1043),#811,.F.);
#1045=CARTESIAN_POINT('',(6.35,4.5,0.));
#1046=DIRECTION('',(0.,-0.707106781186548,0.707106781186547));
#1047=DIRECTION('',(0.,0.707106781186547,0.707106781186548));
#1048=AXIS2_PLACEMENT_3D('',#1045,#1046,#1047);
#1049=PLANE('',#1048);
#1050=CARTESIAN_POINT('',(0.,0.,-4.5));
#1051=DIRECTION('',(0.,-0.707106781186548,0.707106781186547));
#1052=DIRECTION('',(0.,-0.707106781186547,-0.707106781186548));
#1053=AXIS2_PLACEMENT_3D('',#1050,#1051,#1052);
#1054=ELLIPSE('',#1053,8.98025612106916,6.35);
#1055=CARTESIAN_POINT('',(-2.07906228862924,6.,1.5));
#1056=VERTEX_POINT('',#1055);
#1057=CARTESIAN_POINT('',(-2.65133928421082,5.77,1.27));
#1058=VERTEX_POINT('',#1057);
#1059=EDGE_CURVE('E457',#1056,#1058,#1054,.T.);
#1060=ORIENTED_EDGE('',*,*,#1059,.F.);
#1061=DIRECTION('',(-1.,0.,0.));
#1062=VECTOR('',#1061,1.);
#1063=CARTESIAN_POINT('',(6.35,6.,1.5));
#1064=LINE('',#1063,#1062);
#1065=EDGE_CURVE('E603',#131,#1056,#1064,.T.);
#1066=ORIENTED_EDGE('',*,*,#1065,.F.);
#1067=DIRECTION('',(0.577350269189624,0.577350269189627,0.577350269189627));
#1068=VECTOR('',#1067,1.);
#1069=CARTESIAN_POINT('',(-4.11666666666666,1.88333333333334,-2.6166666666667));
#1070=LINE('',#1069,#1068);
#1071=EDGE_CURVE('E647',#647,#131,#1070,.T.);
#1072=ORIENTED_EDGE('',*,*,#1071,.F.);
#1073=ORIENTED_EDGE('',*,*,#648,.F.);
#1074=CARTESIAN_POINT('',(0.,0.,-4.5));
#1075=DIRECTION('',(0.,-0.707106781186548,0.707106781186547));
#1076=DIRECTION('',(0.,0.707106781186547,0.707106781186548));
#1077=AXIS2_PLACEMENT_3D('',#1074,#1075,#1076);
#1078=ELLIPSE('',#1077,8.98025612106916,6.35);
#1079=EDGE_CURVE('E409',#1058,#639,#1078,.T.);
#1080=ORIENTED_EDGE('',*,*,#1079,.F.);
#1081=EDGE_LOOP('',(#1060,#1066,#1072,#1073,#1080));
#1082=FACE_BOUND('',#1081,.T.);
#1083=ADVANCED_FACE('F1447',(#1082),#1049,.F.);
#1084=CARTESIAN_POINT('',(6.35,6.,1.5));
#1085=DIRECTION('',(0.,0.707106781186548,0.707106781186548));
#1086=DIRECTION('',(0.,0.707106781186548,-0.707106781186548));
#1087=AXIS2_PLACEMENT_3D('',#1084,#1085,#1086);
#1088=PLANE('',#1087);
#1089=CARTESIAN_POINT('',(0.,0.,7.5));
#1090=DIRECTION('',(0.,0.707106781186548,0.707106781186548));
#1091=DIRECTION('',(0.,0.707106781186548,-0.707106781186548));
#1092=AXIS2_PLACEMENT_3D('',#1089,#1090,#1091);
#1093=ELLIPSE('',#1092,8.98025612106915,6.35);
#1094=CARTESIAN_POINT('',(-1.22865780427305,6.22999999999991,1.27));
#1095=VERTEX_POINT('',#1094);
#1096=EDGE_CURVE('E453',#1095,#1056,#1093,.T.);
#1097=ORIENTED_EDGE('',*,*,#1096,.F.);
#1098=CARTESIAN_POINT('',(0.,0.,7.5));
#1099=DIRECTION('',(0.,0.707106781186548,0.707106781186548));
#1100=DIRECTION('',(0.,-0.707106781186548,0.707106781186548));
#1101=AXIS2_PLACEMENT_3D('',#1098,#1099,#1100);
#1102=ELLIPSE('',#1101,8.98025612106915,6.35);
#1103=EDGE_CURVE('E663',#187,#1095,#1102,.T.);
#1104=ORIENTED_EDGE('',*,*,#1103,.F.);
#1105=ORIENTED_EDGE('',*,*,#188,.F.);
#1106=ORIENTED_EDGE('',*,*,#1065,.T.);
#1107=EDGE_LOOP('',(#1097,#1104,#1105,#1106));
#1108=FACE_BOUND('',#1107,.T.);
#1109=ADVANCED_FACE('F1450',(#1108),#1088,.F.);
#1110=CARTESIAN_POINT('',(6.35,-6.,1.5));
#1111=DIRECTION('',(0.,-0.707106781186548,0.707106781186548));
#1112=DIRECTION('',(0.,0.707106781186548,0.707106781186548));
#1113=AXIS2_PLACEMENT_3D('',#1110,#1111,#1112);
#1114=PLANE('',#1113);
#1115=CARTESIAN_POINT('',(0.,0.,7.5));
#1116=DIRECTION('',(0.,-0.707106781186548,0.707106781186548));
#1117=DIRECTION('',(0.,-0.707106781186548,-0.707106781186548));
#1118=AXIS2_PLACEMENT_3D('',#1115,#1116,#1117);
#1119=ELLIPSE('',#1118,8.98025612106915,6.35);
#1120=CARTESIAN_POINT('',(-2.07906228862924,-6.,1.5));
#1121=VERTEX_POINT('',#1120);
#1122=CARTESIAN_POINT('',(-1.22865780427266,-6.23,1.27));
#1123=VERTEX_POINT('',#1122);
#1124=EDGE_CURVE('E449',#1121,#1123,#1119,.T.);
#1125=ORIENTED_EDGE('',*,*,#1124,.F.);
#1126=DIRECTION('',(-1.,0.,0.));
#1127=VECTOR('',#1126,1.);
#1128=CARTESIAN_POINT('',(6.35,-6.,1.5));
#1129=LINE('',#1128,#1127);
#1130=EDGE_CURVE('E599',#90,#1121,#1129,.T.);
#1131=ORIENTED_EDGE('',*,*,#1130,.F.);
#1132=ORIENTED_EDGE('',*,*,#166,.F.);
#1133=CARTESIAN_POINT('',(0.,0.,7.5));
#1134=DIRECTION('',(0.,-0.707106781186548,0.707106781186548));
#1135=DIRECTION('',(0.,0.707106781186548,0.707106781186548));
#1136=AXIS2_PLACEMENT_3D('',#1133,#1134,#1135);
#1137=ELLIPSE('',#1136,8.98025612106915,6.35);
#1138=EDGE_CURVE('E679',#1123,#159,#1137,.T.);
#1139=ORIENTED_EDGE('',*,*,#1138,.F.);
#1140=EDGE_LOOP('',(#1125,#1131,#1132,#1139));
#1141=FACE_BOUND('',#1140,.T.);
#1142=ADVANCED_FACE('F1452',(#1141),#1114,.F.);
#1143=CARTESIAN_POINT('',(6.35,-4.5,0.));
#1144=DIRECTION('',(0.,0.707106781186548,0.707106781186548));
#1145=DIRECTION('',(0.,0.707106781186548,-0.707106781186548));
#1146=AXIS2_PLACEMENT_3D('',#1143,#1144,#1145);
#1147=PLANE('',#1146);
#1148=CARTESIAN_POINT('',(0.,0.,-4.5));
#1149=DIRECTION('',(0.,0.707106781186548,0.707106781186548));
#1150=DIRECTION('',(0.,0.707106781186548,-0.707106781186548));
#1151=AXIS2_PLACEMENT_3D('',#1148,#1149,#1150);
#1152=ELLIPSE('',#1151,8.98025612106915,6.35);
#1153=CARTESIAN_POINT('',(-2.65133928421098,-5.77,1.27));
#1154=VERTEX_POINT('',#1153);
#1155=EDGE_CURVE('E445',#1154,#1121,#1152,.T.);
#1156=ORIENTED_EDGE('',*,*,#1155,.F.);
#1157=CARTESIAN_POINT('',(0.,0.,-4.5));
#1158=DIRECTION('',(0.,0.707106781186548,0.707106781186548));
#1159=DIRECTION('',(0.,-0.707106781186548,0.707106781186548));
#1160=AXIS2_PLACEMENT_3D('',#1157,#1158,#1159);
#1161=ELLIPSE('',#1160,8.98025612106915,6.35);
#1162=EDGE_CURVE('E703',#232,#1154,#1161,.T.);
#1163=ORIENTED_EDGE('',*,*,#1162,.F.);
#1164=ORIENTED_EDGE('',*,*,#233,.F.);
#1165=DIRECTION('',(-0.577350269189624,0.577350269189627,-0.577350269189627));
#1166=VECTOR('',#1165,1.);
#1167=CARTESIAN_POINT('',(0.11666666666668,-6.11666666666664,1.61666666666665));
#1168=LINE('',#1167,#1166);
#1169=EDGE_CURVE('E695',#90,#224,#1168,.T.);
#1170=ORIENTED_EDGE('',*,*,#1169,.F.);
#1171=ORIENTED_EDGE('',*,*,#1130,.T.);
#1172=EDGE_LOOP('',(#1156,#1163,#1164,#1170,#1171));
#1173=FACE_BOUND('',#1172,.T.);
#1174=ADVANCED_FACE('F1458',(#1173),#1147,.F.);
#1175=CARTESIAN_POINT('',(0.,0.,-4.5));
#1176=DIRECTION('',(0.,-0.707106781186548,0.707106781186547));
#1177=DIRECTION('',(0.,-0.707106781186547,-0.707106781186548));
#1178=AXIS2_PLACEMENT_3D('',#1175,#1176,#1177);
#1179=ELLIPSE('',#1178,8.98025612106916,6.35);
#1180=CARTESIAN_POINT('',(2.65133928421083,5.77,1.27));
#1181=VERTEX_POINT('',#1180);
#1182=CARTESIAN_POINT('',(2.07906228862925,6.,1.5));
#1183=VERTEX_POINT('',#1182);
#1184=EDGE_CURVE('E416',#1181,#1183,#1179,.T.);
#1185=ORIENTED_EDGE('',*,*,#1184,.F.);
#1186=CARTESIAN_POINT('',(0.,0.,-4.5));
#1187=DIRECTION('',(0.,-0.707106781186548,0.707106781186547));
#1188=DIRECTION('',(0.,0.707106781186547,0.707106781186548));
#1189=AXIS2_PLACEMENT_3D('',#1186,#1187,#1188);
#1190=ELLIPSE('',#1189,8.98025612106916,6.35);
#1191=EDGE_CURVE('E635',#619,#1181,#1190,.T.);
#1192=ORIENTED_EDGE('',*,*,#1191,.F.);
#1193=ORIENTED_EDGE('',*,*,#620,.F.);
#1194=DIRECTION('',(0.577350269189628,-0.577350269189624,-0.577350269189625));
#1195=VECTOR('',#1194,1.);
#1196=CARTESIAN_POINT('',(5.11666666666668,0.883333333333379,-3.61666666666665));
#1197=LINE('',#1196,#1195);
#1198=EDGE_CURVE('E640',#131,#611,#1197,.T.);
#1199=ORIENTED_EDGE('',*,*,#1198,.F.);
#1200=EDGE_CURVE('E600',#1183,#131,#1064,.T.);
#1201=ORIENTED_EDGE('',*,*,#1200,.F.);
#1202=EDGE_LOOP('',(#1185,#1192,#1193,#1199,#1201));
#1203=FACE_BOUND('',#1202,.T.);
#1204=ADVANCED_FACE('F1464',(#1203),#1049,.F.);
#1205=CARTESIAN_POINT('',(0.,0.,7.5));
#1206=DIRECTION('',(0.,0.707106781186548,0.707106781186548));
#1207=DIRECTION('',(0.,0.707106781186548,-0.707106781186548));
#1208=AXIS2_PLACEMENT_3D('',#1205,#1206,#1207);
#1209=ELLIPSE('',#1208,8.98025612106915,6.35);
#1210=CARTESIAN_POINT('',(1.22865780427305,6.22999999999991,1.27));
#1211=VERTEX_POINT('',#1210);
#1212=EDGE_CURVE('E404',#1183,#1211,#1209,.T.);
#1213=ORIENTED_EDGE('',*,*,#1212,.F.);
#1214=ORIENTED_EDGE('',*,*,#1200,.T.);
#1215=ORIENTED_EDGE('',*,*,#132,.F.);
#1216=CARTESIAN_POINT('',(0.,0.,7.5));
#1217=DIRECTION('',(0.,0.707106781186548,0.707106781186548));
#1218=DIRECTION('',(0.,-0.707106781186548,0.707106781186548));
#1219=AXIS2_PLACEMENT_3D('',#1216,#1217,#1218);
#1220=ELLIPSE('',#1219,8.98025612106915,6.35);
#1221=EDGE_CURVE('E389',#1211,#123,#1220,.T.);
#1222=ORIENTED_EDGE('',*,*,#1221,.F.);
#1223=EDGE_LOOP('',(#1213,#1214,#1215,#1222));
#1224=FACE_BOUND('',#1223,.T.);
#1225=ADVANCED_FACE('F403',(#1224),#1088,.F.);
#1226=CARTESIAN_POINT('',(0.,0.,7.5));
#1227=DIRECTION('',(0.,-0.707106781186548,0.707106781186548));
#1228=DIRECTION('',(0.,-0.707106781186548,-0.707106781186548));
#1229=AXIS2_PLACEMENT_3D('',#1226,#1227,#1228);
#1230=ELLIPSE('',#1229,8.98025612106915,6.35);
#1231=CARTESIAN_POINT('',(1.22865780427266,-6.23,1.27));
#1232=VERTEX_POINT('',#1231);
#1233=CARTESIAN_POINT('',(2.07906228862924,-6.,1.5));
#1234=VERTEX_POINT('',#1233);
#1235=EDGE_CURVE('E418',#1232,#1234,#1230,.T.);
#1236=ORIENTED_EDGE('',*,*,#1235,.F.);
#1237=CARTESIAN_POINT('',(0.,0.,7.5));
#1238=DIRECTION('',(0.,-0.707106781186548,0.707106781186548));
#1239=DIRECTION('',(0.,0.707106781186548,0.707106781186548));
#1240=AXIS2_PLACEMENT_3D('',#1237,#1238,#1239);
#1241=ELLIPSE('',#1240,8.98025612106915,6.35);
#1242=EDGE_CURVE('E667',#98,#1232,#1241,.T.);
#1243=ORIENTED_EDGE('',*,*,#1242,.F.);
#1244=ORIENTED_EDGE('',*,*,#99,.F.);
#1245=EDGE_CURVE('E596',#1234,#90,#1129,.T.);
#1246=ORIENTED_EDGE('',*,*,#1245,.F.);
#1247=EDGE_LOOP('',(#1236,#1243,#1244,#1246));
#1248=FACE_BOUND('',#1247,.T.);
#1249=ADVANCED_FACE('F1461',(#1248),#1114,.F.);
#1250=CARTESIAN_POINT('',(0.,0.,-4.5));
#1251=DIRECTION('',(0.,0.707106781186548,0.707106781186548));
#1252=DIRECTION('',(0.,0.707106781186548,-0.707106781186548));
#1253=AXIS2_PLACEMENT_3D('',#1250,#1251,#1252);
#1254=ELLIPSE('',#1253,8.98025612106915,6.35);
#1255=CARTESIAN_POINT('',(2.65133928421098,-5.77,1.27));
#1256=VERTEX_POINT('',#1255);
#1257=EDGE_CURVE('E1059',#1234,#1256,#1254,.T.);
#1258=ORIENTED_EDGE('',*,*,#1257,.F.);
#1259=ORIENTED_EDGE('',*,*,#1245,.T.);
#1260=DIRECTION('',(-0.577350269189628,-0.577350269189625,0.577350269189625));
#1261=VECTOR('',#1260,1.);
#1262=CARTESIAN_POINT('',(0.883333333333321,-5.11666666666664,0.616666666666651));
#1263=LINE('',#1262,#1261);
#1264=EDGE_CURVE('E688',#49,#90,#1263,.T.);
#1265=ORIENTED_EDGE('',*,*,#1264,.F.);
#1266=ORIENTED_EDGE('',*,*,#50,.F.);
#1267=CARTESIAN_POINT('',(0.,0.,-4.5));
#1268=DIRECTION('',(0.,0.707106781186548,0.707106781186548));
#1269=DIRECTION('',(0.,-0.707106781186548,0.707106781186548));
#1270=AXIS2_PLACEMENT_3D('',#1267,#1268,#1269);
#1271=ELLIPSE('',#1270,8.98025612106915,6.35);
#1272=EDGE_CURVE('E683',#1256,#41,#1271,.T.);
#1273=ORIENTED_EDGE('',*,*,#1272,.F.);
#1274=EDGE_LOOP('',(#1258,#1259,#1265,#1266,#1273));
#1275=FACE_BOUND('',#1274,.T.);
#1276=ADVANCED_FACE('F1470',(#1275),#1147,.F.);
#1277=CARTESIAN_POINT('',(0.,0.,46.27));
#1278=DIRECTION('',(0.,0.,1.));
#1279=DIRECTION('',(1.,0.,0.));
#1280=AXIS2_PLACEMENT_3D('',#1277,#1278,#1279);
#1281=CYLINDRICAL_SURFACE('',#1280,6.35);
#1282=ORIENTED_EDGE('',*,*,#240,.T.);
#1283=ORIENTED_EDGE('',*,*,#1162,.T.);
#1284=CARTESIAN_POINT('',(0.,0.,1.27));
#1285=DIRECTION('',(0.,0.,1.));
#1286=DIRECTION('',(1.,0.,0.));
#1287=AXIS2_PLACEMENT_3D('',#1284,#1285,#1286);
#1288=CIRCLE('',#1287,6.35);
#1289=EDGE_CURVE('E1282',#208,#1154,#1288,.T.);
#1290=ORIENTED_EDGE('',*,*,#1289,.F.);
#1291=EDGE_LOOP('',(#1282,#1283,#1290));
#1292=FACE_BOUND('',#1291,.T.);
#1293=ADVANCED_FACE('F1558',(#1292),#1281,.T.);
#1294=ORIENTED_EDGE('',*,*,#190,.T.);
#1295=ORIENTED_EDGE('',*,*,#1103,.T.);
#1296=EDGE_CURVE('E397',#178,#1095,#1288,.T.);
#1297=ORIENTED_EDGE('',*,*,#1296,.F.);
#1298=EDGE_LOOP('',(#1294,#1295,#1297));
#1299=FACE_BOUND('',#1298,.T.);
#1300=ADVANCED_FACE('F1387',(#1299),#1281,.T.);
#1301=ORIENTED_EDGE('',*,*,#357,.T.);
#1302=ORIENTED_EDGE('',*,*,#1032,.T.);
#1303=EDGE_CURVE('E1246',#336,#1024,#1288,.T.);
#1304=ORIENTED_EDGE('',*,*,#1303,.F.);
#1305=EDGE_LOOP('',(#1301,#1302,#1304));
#1306=FACE_BOUND('',#1305,.T.);
#1307=ADVANCED_FACE('F2034',(#1306),#1281,.T.);
#1308=EDGE_CURVE('E1023',#973,#289,#1288,.T.);
#1309=ORIENTED_EDGE('',*,*,#1308,.F.);
#1310=ORIENTED_EDGE('',*,*,#989,.T.);
#1311=ORIENTED_EDGE('',*,*,#301,.T.);
#1312=EDGE_LOOP('',(#1309,#1310,#1311));
#1313=FACE_BOUND('',#1312,.T.);
#1314=ADVANCED_FACE('F2151',(#1313),#1281,.T.);
#1315=EDGE_CURVE('E1017',#883,#429,#1288,.T.);
#1316=ORIENTED_EDGE('',*,*,#1315,.F.);
#1317=ORIENTED_EDGE('',*,*,#893,.T.);
#1318=ORIENTED_EDGE('',*,*,#441,.T.);
#1319=EDGE_LOOP('',(#1316,#1317,#1318));
#1320=FACE_BOUND('',#1319,.T.);
#1321=ADVANCED_FACE('F2070',(#1320),#1281,.T.);
#1322=EDGE_CURVE('E1291',#1256,#30,#1288,.T.);
#1323=ORIENTED_EDGE('',*,*,#1322,.F.);
#1324=ORIENTED_EDGE('',*,*,#1272,.T.);
#1325=ORIENTED_EDGE('',*,*,#42,.T.);
#1326=EDGE_LOOP('',(#1323,#1324,#1325));
#1327=FACE_BOUND('',#1326,.T.);
#1328=ADVANCED_FACE('F2135',(#1327),#1281,.T.);
#1329=EDGE_CURVE('E1022',#818,#533,#1288,.T.);
#1330=ORIENTED_EDGE('',*,*,#1329,.F.);
#1331=ORIENTED_EDGE('',*,*,#834,.T.);
#1332=ORIENTED_EDGE('',*,*,#538,.T.);
#1333=EDGE_LOOP('',(#1330,#1331,#1332));
#1334=FACE_BOUND('',#1333,.T.);
#1335=ADVANCED_FACE('F1194',(#1334),#1281,.T.);
#1336=EDGE_CURVE('E386',#1211,#117,#1288,.T.);
#1337=ORIENTED_EDGE('',*,*,#1336,.F.);
#1338=ORIENTED_EDGE('',*,*,#1221,.T.);
#1339=ORIENTED_EDGE('',*,*,#124,.T.);
#1340=EDGE_LOOP('',(#1337,#1338,#1339));
#1341=FACE_BOUND('',#1340,.T.);
#1342=ADVANCED_FACE('F388',(#1341),#1281,.T.);
#1343=ORIENTED_EDGE('',*,*,#522,.T.);
#1344=ORIENTED_EDGE('',*,*,#761,.T.);
#1345=EDGE_CURVE('E1024',#497,#753,#1288,.T.);
#1346=ORIENTED_EDGE('',*,*,#1345,.F.);
#1347=EDGE_LOOP('',(#1343,#1344,#1346));
#1348=FACE_BOUND('',#1347,.T.);
#1349=ADVANCED_FACE('F2112',(#1348),#1281,.T.);
#1350=EDGE_CURVE('E1249',#906,#401,#1288,.T.);
#1351=ORIENTED_EDGE('',*,*,#1350,.F.);
#1352=ORIENTED_EDGE('',*,*,#917,.T.);
#1353=ORIENTED_EDGE('',*,*,#406,.T.);
#1354=EDGE_LOOP('',(#1351,#1352,#1353));
#1355=FACE_BOUND('',#1354,.T.);
#1356=ADVANCED_FACE('F1258',(#1355),#1281,.T.);
#1357=EDGE_CURVE('E1285',#1123,#150,#1288,.T.);
#1358=ORIENTED_EDGE('',*,*,#1357,.F.);
#1359=ORIENTED_EDGE('',*,*,#1138,.T.);
#1360=ORIENTED_EDGE('',*,*,#160,.T.);
#1361=EDGE_LOOP('',(#1358,#1359,#1360));
#1362=FACE_BOUND('',#1361,.T.);
#1363=ADVANCED_FACE('F1548',(#1362),#1281,.T.);
#1364=EDGE_CURVE('E400',#1058,#633,#1288,.T.);
#1365=ORIENTED_EDGE('',*,*,#1364,.F.);
#1366=ORIENTED_EDGE('',*,*,#1079,.T.);
#1367=ORIENTED_EDGE('',*,*,#640,.T.);
#1368=EDGE_LOOP('',(#1365,#1366,#1367));
#1369=FACE_BOUND('',#1368,.T.);
#1370=ADVANCED_FACE('F1545',(#1369),#1281,.T.);
#1371=EDGE_CURVE('E1256',#1002,#256,#1288,.T.);
#1372=ORIENTED_EDGE('',*,*,#1371,.F.);
#1373=ORIENTED_EDGE('',*,*,#1013,.T.);
#1374=ORIENTED_EDGE('',*,*,#266,.T.);
#1375=EDGE_LOOP('',(#1372,#1373,#1374));
#1376=FACE_BOUND('',#1375,.T.);
#1377=ADVANCED_FACE('F1547',(#1376),#1281,.T.);
#1378=ORIENTED_EDGE('',*,*,#681,.T.);
#1379=ORIENTED_EDGE('',*,*,#959,.T.);
#1380=EDGE_CURVE('E1273',#669,#949,#1288,.T.);
#1381=ORIENTED_EDGE('',*,*,#1380,.F.);
#1382=EDGE_LOOP('',(#1378,#1379,#1381));
#1383=FACE_BOUND('',#1382,.T.);
#1384=ADVANCED_FACE('F1541',(#1383),#1281,.T.);
#1385=ORIENTED_EDGE('',*,*,#481,.T.);
#1386=ORIENTED_EDGE('',*,*,#860,.T.);
#1387=EDGE_CURVE('E1018',#468,#850,#1288,.T.);
#1388=ORIENTED_EDGE('',*,*,#1387,.F.);
#1389=EDGE_LOOP('',(#1385,#1386,#1388));
#1390=FACE_BOUND('',#1389,.T.);
#1391=ADVANCED_FACE('F2078',(#1390),#1281,.T.);
#1392=ORIENTED_EDGE('',*,*,#106,.T.);
#1393=ORIENTED_EDGE('',*,*,#1242,.T.);
#1394=EDGE_CURVE('E1288',#82,#1232,#1288,.T.);
#1395=ORIENTED_EDGE('',*,*,#1394,.F.);
#1396=EDGE_LOOP('',(#1392,#1393,#1395));
#1397=FACE_BOUND('',#1396,.T.);
#1398=ADVANCED_FACE('F2080',(#1397),#1281,.T.);
#1399=ORIENTED_EDGE('',*,*,#586,.T.);
#1400=ORIENTED_EDGE('',*,*,#795,.T.);
#1401=EDGE_CURVE('E1255',#569,#785,#1288,.T.);
#1402=ORIENTED_EDGE('',*,*,#1401,.F.);
#1403=EDGE_LOOP('',(#1399,#1400,#1402));
#1404=FACE_BOUND('',#1403,.T.);
#1405=ADVANCED_FACE('F2085',(#1404),#1281,.T.);
#1406=ORIENTED_EDGE('',*,*,#622,.T.);
#1407=ORIENTED_EDGE('',*,*,#1191,.T.);
#1408=EDGE_CURVE('E396',#599,#1181,#1288,.T.);
#1409=ORIENTED_EDGE('',*,*,#1408,.F.);
#1410=EDGE_LOOP('',(#1406,#1407,#1409));
#1411=FACE_BOUND('',#1410,.T.);
#1412=ADVANCED_FACE('F2466',(#1411),#1281,.T.);
#1413=EDGE_CURVE('E399',#722,#692,#1288,.T.);
#1414=ORIENTED_EDGE('',*,*,#1413,.F.);
#1415=ORIENTED_EDGE('',*,*,#737,.T.);
#1416=ORIENTED_EDGE('',*,*,#697,.T.);
#1417=EDGE_LOOP('',(#1414,#1415,#1416));
#1418=FACE_BOUND('',#1417,.T.);
#1419=ADVANCED_FACE('F1086',(#1418),#1281,.T.);
#1420=CARTESIAN_POINT('',(0.,0.,26.27));
#1421=DIRECTION('',(0.,0.,1.));
#1422=DIRECTION('',(1.,0.,0.));
#1423=AXIS2_PLACEMENT_3D('',#1420,#1421,#1422);
#1424=PLANE('',#1423);
#1425=CARTESIAN_POINT('',(0.,0.,26.27));
#1426=DIRECTION('',(0.,0.,1.));
#1427=DIRECTION('',(1.,0.,0.));
#1428=AXIS2_PLACEMENT_3D('',#1425,#1426,#1427);
#1429=CIRCLE('',#1428,8.8);
#1430=CARTESIAN_POINT('',(8.8,0.,26.27));
#1431=VERTEX_POINT('',#1430);
#1432=EDGE_CURVE('E1063',#1431,#1431,#1429,.T.);
#1433=ORIENTED_EDGE('',*,*,#1432,.T.);
#1434=EDGE_LOOP('',(#1433));
#1435=FACE_BOUND('',#1434,.T.);
#1436=DIRECTION('',(0.86602540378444,-0.5,0.));
#1437=VECTOR('',#1436,1.);
#1438=CARTESIAN_POINT('',(-5.,-2.88675134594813,26.27));
#1439=LINE('',#1438,#1437);
#1440=CARTESIAN_POINT('',(-5.,-2.88675134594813,26.27));
#1441=VERTEX_POINT('',#1440);
#1442=CARTESIAN_POINT('',(0.,-5.77350269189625,26.27));
#1443=VERTEX_POINT('',#1442);
#1444=EDGE_CURVE('E952',#1441,#1443,#1439,.T.);
#1445=ORIENTED_EDGE('',*,*,#1444,.F.);
#1446=DIRECTION('',(0.,-1.,0.));
#1447=VECTOR('',#1446,1.);
#1448=CARTESIAN_POINT('',(-5.,2.88675134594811,26.27));
#1449=LINE('',#1448,#1447);
#1450=CARTESIAN_POINT('',(-5.,2.88675134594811,26.27));
#1451=VERTEX_POINT('',#1450);
#1452=EDGE_CURVE('E971',#1451,#1441,#1449,.T.);
#1453=ORIENTED_EDGE('',*,*,#1452,.F.);
#1454=DIRECTION('',(0.866025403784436,0.5,0.));
#1455=VECTOR('',#1454,1.);
#1456=CARTESIAN_POINT('',(-5.,2.88675134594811,26.27));
#1457=LINE('',#1456,#1455);
#1458=CARTESIAN_POINT('',(0.,5.77350269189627,26.27));
#1459=VERTEX_POINT('',#1458);
#1460=EDGE_CURVE('E967',#1451,#1459,#1457,.T.);
#1461=ORIENTED_EDGE('',*,*,#1460,.T.);
#1462=DIRECTION('',(-0.866025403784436,0.5,0.));
#1463=VECTOR('',#1462,1.);
#1464=CARTESIAN_POINT('',(5.,2.88675134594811,26.27));
#1465=LINE('',#1464,#1463);
#1466=CARTESIAN_POINT('',(5.,2.88675134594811,26.27));
#1467=VERTEX_POINT('',#1466);
#1468=EDGE_CURVE('E963',#1467,#1459,#1465,.T.);
#1469=ORIENTED_EDGE('',*,*,#1468,.F.);
#1470=DIRECTION('',(0.,-1.,0.));
#1471=VECTOR('',#1470,1.);
#1472=CARTESIAN_POINT('',(5.,2.88675134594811,26.27));
#1473=LINE('',#1472,#1471);
#1474=CARTESIAN_POINT('',(5.,-2.88675134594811,26.27));
#1475=VERTEX_POINT('',#1474);
#1476=EDGE_CURVE('E959',#1467,#1475,#1473,.T.);
#1477=ORIENTED_EDGE('',*,*,#1476,.T.);
#1478=DIRECTION('',(-0.866025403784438,-0.5,0.));
#1479=VECTOR('',#1478,1.);
#1480=CARTESIAN_POINT('',(5.,-2.88675134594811,26.27));
#1481=LINE('',#1480,#1479);
#1482=EDGE_CURVE('E955',#1475,#1443,#1481,.T.);
#1483=ORIENTED_EDGE('',*,*,#1482,.T.);
#1484=EDGE_LOOP('',(#1445,#1453,#1461,#1469,#1477,#1483));
#1485=FACE_BOUND('',#1484,.T.);
#1486=ADVANCED_FACE('F1083',(#1435,#1485),#1424,.T.);
#1487=CARTESIAN_POINT('',(0.,0.,46.27));
#1488=DIRECTION('',(0.,0.,1.));
#1489=DIRECTION('',(1.,0.,0.));
#1490=AXIS2_PLACEMENT_3D('',#1487,#1488,#1489);
#1491=CYLINDRICAL_SURFACE('',#1490,10.);
#1492=CARTESIAN_POINT('',(0.,0.,25.5771796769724));
#1493=DIRECTION('',(0.,0.,1.));
#1494=DIRECTION('',(1.,0.,0.));
#1495=AXIS2_PLACEMENT_3D('',#1492,#1493,#1494);
#1496=CIRCLE('',#1495,10.);
#1497=CARTESIAN_POINT('',(10.,0.,25.5771796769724));
#1498=VERTEX_POINT('',#1497);
#1499=EDGE_CURVE('E24',#1498,#1498,#1496,.F.);
#1500=ORIENTED_EDGE('',*,*,#1499,.T.);
#1501=EDGE_LOOP('',(#1500));
#1502=FACE_BOUND('',#1501,.T.);
#1503=CARTESIAN_POINT('',(0.,0.,1.96282032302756));
#1504=DIRECTION('',(0.,0.,-1.));
#1505=DIRECTION('',(-1.,0.,0.));
#1506=AXIS2_PLACEMENT_3D('',#1503,#1504,#1505);
#1507=CIRCLE('',#1506,10.);
#1508=CARTESIAN_POINT('',(-10.,0.,1.96282032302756));
#1509=VERTEX_POINT('',#1508);
#1510=EDGE_CURVE('E1067',#1509,#1509,#1507,.F.);
#1511=ORIENTED_EDGE('',*,*,#1510,.T.);
#1512=EDGE_LOOP('',(#1511));
#1513=FACE_BOUND('',#1512,.T.);
#1514=ADVANCED_FACE('F1074',(#1502,#1513),#1491,.T.);
#1515=CARTESIAN_POINT('',(10.,0.,1.27));
#1516=DIRECTION('',(0.,0.,-1.));
#1517=DIRECTION('',(-1.,0.,0.));
#1518=AXIS2_PLACEMENT_3D('',#1515,#1516,#1517);
#1519=PLANE('',#1518);
#1520=CARTESIAN_POINT('',(0.,0.,1.27));
#1521=DIRECTION('',(0.,0.,-1.));
#1522=DIRECTION('',(-1.,0.,0.));
#1523=AXIS2_PLACEMENT_3D('',#1520,#1521,#1522);
#1524=CIRCLE('',#1523,8.8);
#1525=CARTESIAN_POINT('',(-8.8,0.,1.27));
#1526=VERTEX_POINT('',#1525);
#1527=EDGE_CURVE('E9',#1526,#1526,#1524,.T.);
#1528=ORIENTED_EDGE('',*,*,#1527,.T.);
#1529=EDGE_LOOP('',(#1528));
#1530=FACE_BOUND('',#1529,.T.);
#1531=ORIENTED_EDGE('',*,*,#1322,.T.);
#1532=CARTESIAN_POINT('',(0.,0.,1.27));
#1533=DIRECTION('',(0.,0.,-1.));
#1534=DIRECTION('',(-1.,0.,0.));
#1535=AXIS2_PLACEMENT_3D('',#1532,#1533,#1534);
#1536=CIRCLE('',#1535,6.35);
#1537=EDGE_CURVE('E1206',#569,#30,#1536,.T.);
#1538=ORIENTED_EDGE('',*,*,#1537,.F.);
#1539=ORIENTED_EDGE('',*,*,#1401,.T.);
#1540=EDGE_CURVE('E1201',#818,#785,#1536,.T.);
#1541=ORIENTED_EDGE('',*,*,#1540,.F.);
#1542=ORIENTED_EDGE('',*,*,#1329,.T.);
#1543=EDGE_CURVE('E1197',#468,#533,#1536,.T.);
#1544=ORIENTED_EDGE('',*,*,#1543,.F.);
#1545=ORIENTED_EDGE('',*,*,#1387,.T.);
#1546=EDGE_CURVE('E1200',#883,#850,#1536,.T.);
#1547=ORIENTED_EDGE('',*,*,#1546,.F.);
#1548=ORIENTED_EDGE('',*,*,#1315,.T.);
#1549=EDGE_CURVE('E1204',#497,#429,#1536,.T.);
#1550=ORIENTED_EDGE('',*,*,#1549,.F.);
#1551=ORIENTED_EDGE('',*,*,#1345,.T.);
#1552=EDGE_CURVE('E434',#722,#753,#1536,.T.);
#1553=ORIENTED_EDGE('',*,*,#1552,.F.);
#1554=ORIENTED_EDGE('',*,*,#1413,.T.);
#1555=EDGE_CURVE('E427',#599,#692,#1536,.T.);
#1556=ORIENTED_EDGE('',*,*,#1555,.F.);
#1557=ORIENTED_EDGE('',*,*,#1408,.T.);
#1558=EDGE_CURVE('E415',#1211,#1181,#1536,.T.);
#1559=ORIENTED_EDGE('',*,*,#1558,.F.);
#1560=ORIENTED_EDGE('',*,*,#1336,.T.);
#1561=EDGE_CURVE('E426',#178,#117,#1536,.T.);
#1562=ORIENTED_EDGE('',*,*,#1561,.F.);
#1563=ORIENTED_EDGE('',*,*,#1296,.T.);
#1564=EDGE_CURVE('E432',#1058,#1095,#1536,.T.);
#1565=ORIENTED_EDGE('',*,*,#1564,.F.);
#1566=ORIENTED_EDGE('',*,*,#1364,.T.);
#1567=EDGE_CURVE('E1374',#669,#633,#1536,.T.);
#1568=ORIENTED_EDGE('',*,*,#1567,.F.);
#1569=ORIENTED_EDGE('',*,*,#1380,.T.);
#1570=EDGE_CURVE('E1371',#973,#949,#1536,.T.);
#1571=ORIENTED_EDGE('',*,*,#1570,.F.);
#1572=ORIENTED_EDGE('',*,*,#1308,.T.);
#1573=EDGE_CURVE('E439',#373,#289,#1536,.T.);
#1574=ORIENTED_EDGE('',*,*,#1573,.F.);
#1575=EDGE_CURVE('E1254',#373,#928,#1288,.T.);
#1576=ORIENTED_EDGE('',*,*,#1575,.T.);
#1577=EDGE_CURVE('E435',#906,#928,#1536,.T.);
#1578=ORIENTED_EDGE('',*,*,#1577,.F.);
#1579=ORIENTED_EDGE('',*,*,#1350,.T.);
#1580=EDGE_CURVE('E438',#336,#401,#1536,.T.);
#1581=ORIENTED_EDGE('',*,*,#1580,.F.);
#1582=ORIENTED_EDGE('',*,*,#1303,.T.);
#1583=EDGE_CURVE('E1231',#1002,#1024,#1536,.T.);
#1584=ORIENTED_EDGE('',*,*,#1583,.F.);
#1585=ORIENTED_EDGE('',*,*,#1371,.T.);
#1586=EDGE_CURVE('E1226',#208,#256,#1536,.T.);
#1587=ORIENTED_EDGE('',*,*,#1586,.F.);
#1588=ORIENTED_EDGE('',*,*,#1289,.T.);
#1589=EDGE_CURVE('E1220',#1123,#1154,#1536,.T.);
#1590=ORIENTED_EDGE('',*,*,#1589,.F.);
#1591=ORIENTED_EDGE('',*,*,#1357,.T.);
#1592=EDGE_CURVE('E1216',#82,#150,#1536,.T.);
#1593=ORIENTED_EDGE('',*,*,#1592,.F.);
#1594=ORIENTED_EDGE('',*,*,#1394,.T.);
#1595=EDGE_CURVE('E1211',#1256,#1232,#1536,.T.);
#1596=ORIENTED_EDGE('',*,*,#1595,.F.);
#1597=EDGE_LOOP('',(#1531,#1538,#1539,#1541,#1542,#1544,#1545,#1547,#1548,#1550,#1551,#1553,
#1554,#1556,#1557,#1559,#1560,#1562,#1563,#1565,#1566,#1568,#1569,#1571,#1572,#1574,#1576,#1578,
#1579,#1581,#1582,#1584,#1585,#1587,#1588,#1590,#1591,#1593,#1594,#1596));
#1598=FACE_BOUND('',#1597,.T.);
#1599=ADVANCED_FACE('F422',(#1530,#1598),#1519,.T.);
#1600=ORIENTED_EDGE('',*,*,#390,.T.);
#1601=ORIENTED_EDGE('',*,*,#936,.T.);
#1602=ORIENTED_EDGE('',*,*,#1575,.F.);
#1603=EDGE_LOOP('',(#1600,#1601,#1602));
#1604=FACE_BOUND('',#1603,.T.);
#1605=ADVANCED_FACE('F1122',(#1604),#1281,.T.);
#1606=CARTESIAN_POINT('',(-5.,-2.88675134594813,18.27));
#1607=DIRECTION('',(-0.5,-0.86602540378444,0.));
#1608=DIRECTION('',(-0.86602540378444,0.5,0.));
#1609=AXIS2_PLACEMENT_3D('',#1606,#1607,#1608);
#1610=PLANE('',#1609);
#1611=DIRECTION('',(0.,0.,1.));
#1612=VECTOR('',#1611,1.);
#1613=CARTESIAN_POINT('',(-5.,-2.88675134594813,18.27));
#1614=LINE('',#1613,#1612);
#1615=CARTESIAN_POINT('',(-5.,-2.88675134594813,18.27));
#1616=VERTEX_POINT('',#1615);
#1617=EDGE_CURVE('E1015',#1616,#1441,#1614,.T.);
#1618=ORIENTED_EDGE('',*,*,#1617,.T.);
#1619=ORIENTED_EDGE('',*,*,#1444,.T.);
#1620=DIRECTION('',(0.,0.,1.));
#1621=VECTOR('',#1620,1.);
#1622=CARTESIAN_POINT('',(0.,-5.77350269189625,18.27));
#1623=LINE('',#1622,#1621);
#1624=CARTESIAN_POINT('',(0.,-5.77350269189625,18.27));
#1625=VERTEX_POINT('',#1624);
#1626=EDGE_CURVE('E999',#1625,#1443,#1623,.T.);
#1627=ORIENTED_EDGE('',*,*,#1626,.F.);
#1628=DIRECTION('',(0.86602540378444,-0.5,0.));
#1629=VECTOR('',#1628,1.);
#1630=CARTESIAN_POINT('',(-5.,-2.88675134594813,18.27));
#1631=LINE('',#1630,#1629);
#1632=EDGE_CURVE('E975',#1616,#1625,#1631,.T.);
#1633=ORIENTED_EDGE('',*,*,#1632,.F.);
#1634=EDGE_LOOP('',(#1618,#1619,#1627,#1633));
#1635=FACE_BOUND('',#1634,.T.);
#1636=ADVANCED_FACE('F1092',(#1635),#1610,.F.);
#1637=CARTESIAN_POINT('',(-5.,2.88675134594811,18.27));
#1638=DIRECTION('',(-1.,0.,0.));
#1639=DIRECTION('',(0.,1.,0.));
#1640=AXIS2_PLACEMENT_3D('',#1637,#1638,#1639);
#1641=PLANE('',#1640);
#1642=DIRECTION('',(0.,0.,1.));
#1643=VECTOR('',#1642,1.);
#1644=CARTESIAN_POINT('',(-5.,2.88675134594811,18.27));
#1645=LINE('',#1644,#1643);
#1646=CARTESIAN_POINT('',(-5.,2.88675134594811,18.27));
#1647=VERTEX_POINT('',#1646);
#1648=EDGE_CURVE('E1012',#1647,#1451,#1645,.T.);
#1649=ORIENTED_EDGE('',*,*,#1648,.T.);
#1650=ORIENTED_EDGE('',*,*,#1452,.T.);
#1651=ORIENTED_EDGE('',*,*,#1617,.F.);
#1652=DIRECTION('',(0.,-1.,0.));
#1653=VECTOR('',#1652,1.);
#1654=CARTESIAN_POINT('',(-5.,2.88675134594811,18.27));
#1655=LINE('',#1654,#1653);
#1656=EDGE_CURVE('E995',#1647,#1616,#1655,.T.);
#1657=ORIENTED_EDGE('',*,*,#1656,.F.);
#1658=EDGE_LOOP('',(#1649,#1650,#1651,#1657));
#1659=FACE_BOUND('',#1658,.T.);
#1660=ADVANCED_FACE('F1113',(#1659),#1641,.F.);
#1661=CARTESIAN_POINT('',(-5.,2.88675134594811,18.27));
#1662=DIRECTION('',(0.5,-0.866025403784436,0.));
#1663=DIRECTION('',(-0.866025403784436,-0.5,0.));
#1664=AXIS2_PLACEMENT_3D('',#1661,#1662,#1663);
#1665=PLANE('',#1664);
#1666=DIRECTION('',(0.,0.,1.));
#1667=VECTOR('',#1666,1.);
#1668=CARTESIAN_POINT('',(0.,5.77350269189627,18.27));
#1669=LINE('',#1668,#1667);
#1670=CARTESIAN_POINT('',(0.,5.77350269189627,18.27));
#1671=VERTEX_POINT('',#1670);
#1672=EDGE_CURVE('E1009',#1671,#1459,#1669,.T.);
#1673=ORIENTED_EDGE('',*,*,#1672,.T.);
#1674=ORIENTED_EDGE('',*,*,#1460,.F.);
#1675=ORIENTED_EDGE('',*,*,#1648,.F.);
#1676=DIRECTION('',(0.866025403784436,0.5,0.));
#1677=VECTOR('',#1676,1.);
#1678=CARTESIAN_POINT('',(-5.,2.88675134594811,18.27));
#1679=LINE('',#1678,#1677);
#1680=EDGE_CURVE('E991',#1647,#1671,#1679,.T.);
#1681=ORIENTED_EDGE('',*,*,#1680,.T.);
#1682=EDGE_LOOP('',(#1673,#1674,#1675,#1681));
#1683=FACE_BOUND('',#1682,.T.);
#1684=ADVANCED_FACE('F1110',(#1683),#1665,.T.);
#1685=CARTESIAN_POINT('',(5.,2.88675134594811,18.27));
#1686=DIRECTION('',(0.5,0.866025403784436,0.));
#1687=DIRECTION('',(0.866025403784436,-0.5,0.));
#1688=AXIS2_PLACEMENT_3D('',#1685,#1686,#1687);
#1689=PLANE('',#1688);
#1690=DIRECTION('',(0.,0.,1.));
#1691=VECTOR('',#1690,1.);
#1692=CARTESIAN_POINT('',(5.,2.88675134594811,18.27));
#1693=LINE('',#1692,#1691);
#1694=CARTESIAN_POINT('',(5.,2.88675134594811,18.27));
#1695=VERTEX_POINT('',#1694);
#1696=EDGE_CURVE('E1006',#1695,#1467,#1693,.T.);
#1697=ORIENTED_EDGE('',*,*,#1696,.T.);
#1698=ORIENTED_EDGE('',*,*,#1468,.T.);
#1699=ORIENTED_EDGE('',*,*,#1672,.F.);
#1700=DIRECTION('',(-0.866025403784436,0.5,0.));
#1701=VECTOR('',#1700,1.);
#1702=CARTESIAN_POINT('',(5.,2.88675134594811,18.27));
#1703=LINE('',#1702,#1701);
#1704=EDGE_CURVE('E987',#1695,#1671,#1703,.T.);
#1705=ORIENTED_EDGE('',*,*,#1704,.F.);
#1706=EDGE_LOOP('',(#1697,#1698,#1699,#1705));
#1707=FACE_BOUND('',#1706,.T.);
#1708=ADVANCED_FACE('F1106',(#1707),#1689,.F.);
#1709=CARTESIAN_POINT('',(5.,2.88675134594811,18.27));
#1710=DIRECTION('',(-1.,0.,0.));
#1711=DIRECTION('',(0.,1.,0.));
#1712=AXIS2_PLACEMENT_3D('',#1709,#1710,#1711);
#1713=PLANE('',#1712);
#1714=DIRECTION('',(0.,0.,1.));
#1715=VECTOR('',#1714,1.);
#1716=CARTESIAN_POINT('',(5.,-2.88675134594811,18.27));
#1717=LINE('',#1716,#1715);
#1718=CARTESIAN_POINT('',(5.,-2.88675134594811,18.27));
#1719=VERTEX_POINT('',#1718);
#1720=EDGE_CURVE('E1003',#1719,#1475,#1717,.T.);
#1721=ORIENTED_EDGE('',*,*,#1720,.T.);
#1722=ORIENTED_EDGE('',*,*,#1476,.F.);
#1723=ORIENTED_EDGE('',*,*,#1696,.F.);
#1724=DIRECTION('',(0.,-1.,0.));
#1725=VECTOR('',#1724,1.);
#1726=CARTESIAN_POINT('',(5.,2.88675134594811,18.27));
#1727=LINE('',#1726,#1725);
#1728=EDGE_CURVE('E983',#1695,#1719,#1727,.T.);
#1729=ORIENTED_EDGE('',*,*,#1728,.T.);
#1730=EDGE_LOOP('',(#1721,#1722,#1723,#1729));
#1731=FACE_BOUND('',#1730,.T.);
#1732=ADVANCED_FACE('F1102',(#1731),#1713,.T.);
#1733=CARTESIAN_POINT('',(5.,-2.88675134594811,18.27));
#1734=DIRECTION('',(-0.5,0.866025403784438,0.));
#1735=DIRECTION('',(0.866025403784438,0.5,0.));
#1736=AXIS2_PLACEMENT_3D('',#1733,#1734,#1735);
#1737=PLANE('',#1736);
#1738=DIRECTION('',(-0.866025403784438,-0.5,0.));
#1739=VECTOR('',#1738,1.);
#1740=CARTESIAN_POINT('',(5.,-2.88675134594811,18.27));
#1741=LINE('',#1740,#1739);
#1742=EDGE_CURVE('E979',#1719,#1625,#1741,.T.);
#1743=ORIENTED_EDGE('',*,*,#1742,.T.);
#1744=ORIENTED_EDGE('',*,*,#1626,.T.);
#1745=ORIENTED_EDGE('',*,*,#1482,.F.);
#1746=ORIENTED_EDGE('',*,*,#1720,.F.);
#1747=EDGE_LOOP('',(#1743,#1744,#1745,#1746));
#1748=FACE_BOUND('',#1747,.T.);
#1749=ADVANCED_FACE('F1095',(#1748),#1737,.T.);
#1750=CARTESIAN_POINT('',(5.,-8.66025403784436,18.27));
#1751=DIRECTION('',(0.,0.,-1.));
#1752=DIRECTION('',(-1.,0.,0.));
#1753=AXIS2_PLACEMENT_3D('',#1750,#1751,#1752);
#1754=PLANE('',#1753);
#1755=ORIENTED_EDGE('',*,*,#1632,.T.);
#1756=ORIENTED_EDGE('',*,*,#1742,.F.);
#1757=ORIENTED_EDGE('',*,*,#1728,.F.);
#1758=ORIENTED_EDGE('',*,*,#1704,.T.);
#1759=ORIENTED_EDGE('',*,*,#1680,.F.);
#1760=ORIENTED_EDGE('',*,*,#1656,.T.);
#1761=EDGE_LOOP('',(#1755,#1756,#1757,#1758,#1759,#1760));
#1762=FACE_BOUND('',#1761,.T.);
#1763=ADVANCED_FACE('F1099',(#1762),#1754,.F.);
#1764=DIRECTION('',(0.577350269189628,-0.577350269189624,-0.577350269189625));
#1765=VECTOR('',#1764,1.);
#1766=CARTESIAN_POINT('',(5.11666666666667,-2.11666666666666,-0.616666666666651));
#1767=LINE('',#1766,#1765);
#1768=CARTESIAN_POINT('',(3.,0.,1.5));
#1769=VERTEX_POINT('',#1768);
#1770=EDGE_CURVE('E1047',#1769,#545,#1767,.T.);
#1771=ORIENTED_EDGE('',*,*,#1770,.T.);
#1772=ORIENTED_EDGE('',*,*,#826,.T.);
#1773=EDGE_CURVE('E914',#57,#1769,#63,.T.);
#1774=ORIENTED_EDGE('',*,*,#1773,.T.);
#1775=EDGE_LOOP('',(#1771,#1772,#1774));
#1776=FACE_BOUND('',#1775,.T.);
#1777=ADVANCED_FACE('F1160',(#1776),#562,.F.);
#1778=ORIENTED_EDGE('',*,*,#1773,.F.);
#1779=DIRECTION('',(-0.577350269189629,0.577350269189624,-0.577350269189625));
#1780=VECTOR('',#1779,1.);
#1781=CARTESIAN_POINT('',(3.11666666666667,-3.11666666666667,1.61666666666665));
#1782=LINE('',#1781,#1780);
#1783=CARTESIAN_POINT('',(1.5,-1.5,0.));
#1784=VERTEX_POINT('',#1783);
#1785=EDGE_CURVE('E738',#57,#1784,#1782,.T.);
#1786=ORIENTED_EDGE('',*,*,#1785,.T.);
#1787=DIRECTION('',(0.577350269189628,0.577350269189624,0.577350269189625));
#1788=VECTOR('',#1787,1.);
#1789=CARTESIAN_POINT('',(-0.116666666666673,-3.11666666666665,-1.61666666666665));
#1790=LINE('',#1789,#1788);
#1791=EDGE_CURVE('E778',#1784,#1769,#1790,.T.);
#1792=ORIENTED_EDGE('',*,*,#1791,.T.);
#1793=EDGE_LOOP('',(#1778,#1786,#1792));
#1794=FACE_BOUND('',#1793,.T.);
#1795=ADVANCED_FACE('F1144',(#1794),#23,.F.);
#1796=ORIENTED_EDGE('',*,*,#1770,.F.);
#1797=EDGE_CURVE('E588',#448,#1769,#866,.T.);
#1798=ORIENTED_EDGE('',*,*,#1797,.F.);
#1799=ORIENTED_EDGE('',*,*,#552,.F.);
#1800=EDGE_LOOP('',(#1796,#1798,#1799));
#1801=FACE_BOUND('',#1800,.T.);
#1802=ADVANCED_FACE('F1157',(#1801),#843,.F.);
#1803=ORIENTED_EDGE('',*,*,#1797,.T.);
#1804=DIRECTION('',(-0.577350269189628,-0.577350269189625,0.577350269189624));
#1805=VECTOR('',#1804,1.);
#1806=CARTESIAN_POINT('',(0.883333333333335,-2.11666666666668,3.61666666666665));
#1807=LINE('',#1806,#1805);
#1808=EDGE_CURVE('E1043',#506,#1769,#1807,.T.);
#1809=ORIENTED_EDGE('',*,*,#1808,.F.);
#1810=ORIENTED_EDGE('',*,*,#507,.F.);
#1811=EDGE_LOOP('',(#1803,#1809,#1810));
#1812=FACE_BOUND('',#1811,.T.);
#1813=ADVANCED_FACE('F1158',(#1812),#876,.F.);
#1814=ORIENTED_EDGE('',*,*,#768,.T.);
#1815=ORIENTED_EDGE('',*,*,#1808,.T.);
#1816=EDGE_CURVE('E1177',#1769,#603,#63,.T.);
#1817=ORIENTED_EDGE('',*,*,#1816,.T.);
#1818=EDGE_LOOP('',(#1814,#1815,#1817));
#1819=FACE_BOUND('',#1818,.T.);
#1820=ADVANCED_FACE('F1147',(#1819),#562,.F.);
#1821=ORIENTED_EDGE('',*,*,#1816,.F.);
#1822=DIRECTION('',(-0.577350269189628,0.577350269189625,-0.577350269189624));
#1823=VECTOR('',#1822,1.);
#1824=CARTESIAN_POINT('',(4.11666666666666,-1.11666666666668,2.61666666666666));
#1825=LINE('',#1824,#1823);
#1826=CARTESIAN_POINT('',(1.5,1.49999999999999,0.));
#1827=VERTEX_POINT('',#1826);
#1828=EDGE_CURVE('E820',#1769,#1827,#1825,.T.);
#1829=ORIENTED_EDGE('',*,*,#1828,.T.);
#1830=DIRECTION('',(0.577350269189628,0.577350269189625,0.577350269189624));
#1831=VECTOR('',#1830,1.);
#1832=CARTESIAN_POINT('',(-1.11666666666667,-1.11666666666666,-2.61666666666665));
#1833=LINE('',#1832,#1831);
#1834=EDGE_CURVE('E860',#1827,#603,#1833,.T.);
#1835=ORIENTED_EDGE('',*,*,#1834,.T.);
#1836=EDGE_LOOP('',(#1821,#1829,#1835));
#1837=FACE_BOUND('',#1836,.T.);
#1838=ADVANCED_FACE('F1130',(#1837),#23,.F.);
#1839=CARTESIAN_POINT('',(-3.,0.,1.5));
#1840=VERTEX_POINT('',#1839);
#1841=EDGE_CURVE('E1350',#1840,#316,#866,.T.);
#1842=ORIENTED_EDGE('',*,*,#1841,.F.);
#1843=DIRECTION('',(0.577350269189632,0.577350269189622,0.577350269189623));
#1844=VECTOR('',#1843,1.);
#1845=CARTESIAN_POINT('',(-5.11666666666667,-2.11666666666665,-0.616666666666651));
#1846=LINE('',#1845,#1844);
#1847=EDGE_CURVE('E797',#346,#1840,#1846,.T.);
#1848=ORIENTED_EDGE('',*,*,#1847,.F.);
#1849=ORIENTED_EDGE('',*,*,#347,.F.);
#1850=EDGE_LOOP('',(#1842,#1848,#1849));
#1851=FACE_BOUND('',#1850,.T.);
#1852=ADVANCED_FACE('F1146',(#1851),#843,.F.);
#1853=DIRECTION('',(-0.577350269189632,0.577350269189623,-0.577350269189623));
#1854=VECTOR('',#1853,1.);
#1855=CARTESIAN_POINT('',(-0.883333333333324,-2.11666666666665,3.6166666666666));
#1856=LINE('',#1855,#1854);
#1857=EDGE_CURVE('E840',#1840,#308,#1856,.T.);
#1858=ORIENTED_EDGE('',*,*,#1857,.F.);
#1859=ORIENTED_EDGE('',*,*,#1841,.T.);
#1860=ORIENTED_EDGE('',*,*,#317,.F.);
#1861=EDGE_LOOP('',(#1858,#1859,#1860));
#1862=FACE_BOUND('',#1861,.T.);
#1863=ADVANCED_FACE('F1153',(#1862),#876,.F.);
#1864=EDGE_CURVE('E901',#216,#1840,#214,.T.);
#1865=ORIENTED_EDGE('',*,*,#1864,.F.);
#1866=ORIENTED_EDGE('',*,*,#1039,.T.);
#1867=ORIENTED_EDGE('',*,*,#1847,.T.);
#1868=EDGE_LOOP('',(#1865,#1866,#1867));
#1869=FACE_BOUND('',#1868,.T.);
#1870=ADVANCED_FACE('F1677',(#1869),#249,.F.);
#1871=DIRECTION('',(0.577350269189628,-0.577350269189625,-0.577350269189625));
#1872=VECTOR('',#1871,1.);
#1873=CARTESIAN_POINT('',(0.116666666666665,-3.11666666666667,-1.6166666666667));
#1874=LINE('',#1873,#1872);
#1875=CARTESIAN_POINT('',(-1.5,-1.5,0.));
#1876=VERTEX_POINT('',#1875);
#1877=EDGE_CURVE('E794',#1840,#1876,#1874,.T.);
#1878=ORIENTED_EDGE('',*,*,#1877,.T.);
#1879=DIRECTION('',(-0.577350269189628,-0.577350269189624,0.577350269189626));
#1880=VECTOR('',#1879,1.);
#1881=CARTESIAN_POINT('',(-3.11666666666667,-3.11666666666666,1.61666666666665));
#1882=LINE('',#1881,#1880);
#1883=EDGE_CURVE('E754',#1876,#216,#1882,.T.);
#1884=ORIENTED_EDGE('',*,*,#1883,.T.);
#1885=ORIENTED_EDGE('',*,*,#1864,.T.);
#1886=EDGE_LOOP('',(#1878,#1884,#1885));
#1887=FACE_BOUND('',#1886,.T.);
#1888=ADVANCED_FACE('F1687',(#1887),#199,.F.);
#1889=EDGE_CURVE('E1331',#1840,#655,#214,.T.);
#1890=ORIENTED_EDGE('',*,*,#1889,.F.);
#1891=ORIENTED_EDGE('',*,*,#1857,.T.);
#1892=ORIENTED_EDGE('',*,*,#981,.T.);
#1893=EDGE_LOOP('',(#1890,#1891,#1892));
#1894=FACE_BOUND('',#1893,.T.);
#1895=ADVANCED_FACE('F1530',(#1894),#249,.F.);
#1896=DIRECTION('',(0.577350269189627,-0.577350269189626,-0.577350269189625));
#1897=VECTOR('',#1896,1.);
#1898=CARTESIAN_POINT('',(1.11666666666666,-1.11666666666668,-2.6166666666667));
#1899=LINE('',#1898,#1897);
#1900=CARTESIAN_POINT('',(-1.5,1.5,0.));
#1901=VERTEX_POINT('',#1900);
#1902=EDGE_CURVE('E876',#655,#1901,#1899,.T.);
#1903=ORIENTED_EDGE('',*,*,#1902,.T.);
#1904=DIRECTION('',(-0.577350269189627,-0.577350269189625,0.577350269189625));
#1905=VECTOR('',#1904,1.);
#1906=CARTESIAN_POINT('',(-4.11666666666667,-1.11666666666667,2.61666666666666));
#1907=LINE('',#1906,#1905);
#1908=EDGE_CURVE('E836',#1901,#1840,#1907,.T.);
#1909=ORIENTED_EDGE('',*,*,#1908,.T.);
#1910=ORIENTED_EDGE('',*,*,#1889,.T.);
#1911=EDGE_LOOP('',(#1903,#1909,#1910));
#1912=FACE_BOUND('',#1911,.T.);
#1913=ADVANCED_FACE('F1513',(#1912),#199,.F.);
#1914=DIRECTION('',(-0.577350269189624,0.577350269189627,-0.577350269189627));
#1915=VECTOR('',#1914,1.);
#1916=CARTESIAN_POINT('',(3.11666666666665,-0.116666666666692,4.61666666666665));
#1917=LINE('',#1916,#1915);
#1918=CARTESIAN_POINT('',(0.,3.,1.5));
#1919=VERTEX_POINT('',#1918);
#1920=EDGE_CURVE('E619',#1919,#647,#1917,.T.);
#1921=ORIENTED_EDGE('',*,*,#1920,.F.);
#1922=EDGE_CURVE('E1365',#1919,#655,#728,.T.);
#1923=ORIENTED_EDGE('',*,*,#1922,.T.);
#1924=ORIENTED_EDGE('',*,*,#656,.F.);
#1925=EDGE_LOOP('',(#1921,#1923,#1924));
#1926=FACE_BOUND('',#1925,.T.);
#1927=ADVANCED_FACE('F1433',(#1926),#713,.F.);
#1928=ORIENTED_EDGE('',*,*,#1922,.F.);
#1929=DIRECTION('',(0.577350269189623,0.577350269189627,0.577350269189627));
#1930=VECTOR('',#1929,1.);
#1931=CARTESIAN_POINT('',(-3.11666666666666,-0.116666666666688,-1.6166666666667));
#1932=LINE('',#1931,#1930);
#1933=EDGE_CURVE('E872',#1901,#1919,#1932,.T.);
#1934=ORIENTED_EDGE('',*,*,#1933,.F.);
#1935=ORIENTED_EDGE('',*,*,#1902,.F.);
#1936=EDGE_LOOP('',(#1928,#1934,#1935));
#1937=FACE_BOUND('',#1936,.T.);
#1938=ADVANCED_FACE('F1495',(#1937),#746,.F.);
#1939=CARTESIAN_POINT('',(0.,-3.,1.5));
#1940=VERTEX_POINT('',#1939);
#1941=EDGE_CURVE('E1357',#1940,#216,#801,.T.);
#1942=ORIENTED_EDGE('',*,*,#1941,.F.);
#1943=DIRECTION('',(0.577350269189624,0.577350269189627,0.577350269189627));
#1944=VECTOR('',#1943,1.);
#1945=CARTESIAN_POINT('',(-1.11666666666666,-4.11666666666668,0.383333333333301));
#1946=LINE('',#1945,#1944);
#1947=EDGE_CURVE('E719',#224,#1940,#1946,.T.);
#1948=ORIENTED_EDGE('',*,*,#1947,.F.);
#1949=ORIENTED_EDGE('',*,*,#225,.F.);
#1950=EDGE_LOOP('',(#1942,#1948,#1949));
#1951=FACE_BOUND('',#1950,.T.);
#1952=ADVANCED_FACE('F1503',(#1951),#778,.F.);
#1953=DIRECTION('',(-0.577350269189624,0.577350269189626,-0.577350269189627));
#1954=VECTOR('',#1953,1.);
#1955=CARTESIAN_POINT('',(1.11666666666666,-4.11666666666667,2.61666666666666));
#1956=LINE('',#1955,#1954);
#1957=EDGE_CURVE('E750',#1940,#1876,#1956,.T.);
#1958=ORIENTED_EDGE('',*,*,#1957,.F.);
#1959=ORIENTED_EDGE('',*,*,#1941,.T.);
#1960=ORIENTED_EDGE('',*,*,#1883,.F.);
#1961=EDGE_LOOP('',(#1958,#1959,#1960));
#1962=FACE_BOUND('',#1961,.T.);
#1963=ADVANCED_FACE('F1511',(#1962),#811,.F.);
#1964=CARTESIAN_POINT('',(0.,0.,1.5));
#1965=VERTEX_POINT('',#1964);
#1966=EDGE_CURVE('E1347',#1965,#1840,#866,.T.);
#1967=ORIENTED_EDGE('',*,*,#1966,.F.);
#1968=DIRECTION('',(0.577350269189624,0.577350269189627,0.577350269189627));
#1969=VECTOR('',#1968,1.);
#1970=CARTESIAN_POINT('',(-2.11666666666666,-2.11666666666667,-0.616666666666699));
#1971=LINE('',#1970,#1969);
#1972=EDGE_CURVE('E790',#1876,#1965,#1971,.T.);
#1973=ORIENTED_EDGE('',*,*,#1972,.F.);
#1974=ORIENTED_EDGE('',*,*,#1877,.F.);
#1975=EDGE_LOOP('',(#1967,#1973,#1974));
#1976=FACE_BOUND('',#1975,.T.);
#1977=ADVANCED_FACE('F1738',(#1976),#843,.F.);
#1978=DIRECTION('',(-0.577350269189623,0.577350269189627,-0.577350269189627));
#1979=VECTOR('',#1978,1.);
#1980=CARTESIAN_POINT('',(2.11666666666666,-2.11666666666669,3.61666666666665));
#1981=LINE('',#1980,#1979);
#1982=EDGE_CURVE('E832',#1965,#1901,#1981,.T.);
#1983=ORIENTED_EDGE('',*,*,#1982,.F.);
#1984=ORIENTED_EDGE('',*,*,#1966,.T.);
#1985=ORIENTED_EDGE('',*,*,#1908,.F.);
#1986=EDGE_LOOP('',(#1983,#1984,#1985));
#1987=FACE_BOUND('',#1986,.T.);
#1988=ADVANCED_FACE('F1439',(#1987),#876,.F.);
#1989=ORIENTED_EDGE('',*,*,#1920,.T.);
#1990=ORIENTED_EDGE('',*,*,#1071,.T.);
#1991=EDGE_CURVE('E1324',#1919,#131,#88,.T.);
#1992=ORIENTED_EDGE('',*,*,#1991,.F.);
#1993=EDGE_LOOP('',(#1989,#1990,#1992));
#1994=FACE_BOUND('',#1993,.T.);
#1995=ADVANCED_FACE('F1402',(#1994),#143,.F.);
#1996=ORIENTED_EDGE('',*,*,#1991,.T.);
#1997=ORIENTED_EDGE('',*,*,#1198,.T.);
#1998=DIRECTION('',(-0.577350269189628,-0.577350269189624,0.577350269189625));
#1999=VECTOR('',#1998,1.);
#2000=CARTESIAN_POINT('',(-2.11666666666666,0.883333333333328,3.61666666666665));
#2001=LINE('',#2000,#1999);
#2002=EDGE_CURVE('E615',#611,#1919,#2001,.T.);
#2003=ORIENTED_EDGE('',*,*,#2002,.T.);
#2004=EDGE_LOOP('',(#1996,#1997,#2003));
#2005=FACE_BOUND('',#2004,.T.);
#2006=ADVANCED_FACE('F1137',(#2005),#73,.F.);
#2007=EDGE_CURVE('E896',#90,#1940,#88,.T.);
#2008=ORIENTED_EDGE('',*,*,#2007,.F.);
#2009=ORIENTED_EDGE('',*,*,#1169,.T.);
#2010=ORIENTED_EDGE('',*,*,#1947,.T.);
#2011=EDGE_LOOP('',(#2008,#2009,#2010));
#2012=FACE_BOUND('',#2011,.T.);
#2013=ADVANCED_FACE('F1406',(#2012),#143,.F.);
#2014=DIRECTION('',(0.577350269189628,-0.577350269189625,-0.577350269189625));
#2015=VECTOR('',#2014,1.);
#2016=CARTESIAN_POINT('',(2.11666666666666,-5.11666666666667,-0.616666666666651));
#2017=LINE('',#2016,#2015);
#2018=EDGE_CURVE('E715',#1940,#49,#2017,.T.);
#2019=ORIENTED_EDGE('',*,*,#2018,.T.);
#2020=ORIENTED_EDGE('',*,*,#1264,.T.);
#2021=ORIENTED_EDGE('',*,*,#2007,.T.);
#2022=EDGE_LOOP('',(#2019,#2020,#2021));
#2023=FACE_BOUND('',#2022,.T.);
#2024=ADVANCED_FACE('F1396',(#2023),#73,.F.);
#2025=EDGE_CURVE('E1318',#1940,#1965,#88,.T.);
#2026=ORIENTED_EDGE('',*,*,#2025,.F.);
#2027=ORIENTED_EDGE('',*,*,#1957,.T.);
#2028=ORIENTED_EDGE('',*,*,#1972,.T.);
#2029=EDGE_LOOP('',(#2026,#2027,#2028));
#2030=FACE_BOUND('',#2029,.T.);
#2031=ADVANCED_FACE('F1405',(#2030),#143,.F.);
#2032=DIRECTION('',(0.577350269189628,-0.577350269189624,-0.577350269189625));
#2033=VECTOR('',#2032,1.);
#2034=CARTESIAN_POINT('',(3.11666666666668,-3.11666666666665,-1.61666666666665));
#2035=LINE('',#2034,#2033);
#2036=EDGE_CURVE('E786',#1965,#1784,#2035,.T.);
#2037=ORIENTED_EDGE('',*,*,#2036,.T.);
#2038=DIRECTION('',(-0.577350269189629,-0.577350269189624,0.577350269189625));
#2039=VECTOR('',#2038,1.);
#2040=CARTESIAN_POINT('',(-0.116666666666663,-3.11666666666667,1.61666666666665));
#2041=LINE('',#2040,#2039);
#2042=EDGE_CURVE('E746',#1784,#1940,#2041,.T.);
#2043=ORIENTED_EDGE('',*,*,#2042,.T.);
#2044=ORIENTED_EDGE('',*,*,#2025,.T.);
#2045=EDGE_LOOP('',(#2037,#2043,#2044));
#2046=FACE_BOUND('',#2045,.T.);
#2047=ADVANCED_FACE('F1408',(#2046),#73,.F.);
#2048=EDGE_CURVE('E1321',#1965,#1919,#88,.T.);
#2049=ORIENTED_EDGE('',*,*,#2048,.F.);
#2050=ORIENTED_EDGE('',*,*,#1982,.T.);
#2051=ORIENTED_EDGE('',*,*,#1933,.T.);
#2052=EDGE_LOOP('',(#2049,#2050,#2051));
#2053=FACE_BOUND('',#2052,.T.);
#2054=ADVANCED_FACE('F1414',(#2053),#143,.F.);
#2055=DIRECTION('',(0.577350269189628,-0.577350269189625,-0.577350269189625));
#2056=VECTOR('',#2055,1.);
#2057=CARTESIAN_POINT('',(4.11666666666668,-1.11666666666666,-2.61666666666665));
#2058=LINE('',#2057,#2056);
#2059=EDGE_CURVE('E868',#1919,#1827,#2058,.T.);
#2060=ORIENTED_EDGE('',*,*,#2059,.T.);
#2061=DIRECTION('',(-0.577350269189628,-0.577350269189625,0.577350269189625));
#2062=VECTOR('',#2061,1.);
#2063=CARTESIAN_POINT('',(-1.11666666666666,-1.11666666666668,2.61666666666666));
#2064=LINE('',#2063,#2062);
#2065=EDGE_CURVE('E828',#1827,#1965,#2064,.T.);
#2066=ORIENTED_EDGE('',*,*,#2065,.T.);
#2067=ORIENTED_EDGE('',*,*,#2048,.T.);
#2068=EDGE_LOOP('',(#2060,#2066,#2067));
#2069=FACE_BOUND('',#2068,.T.);
#2070=ADVANCED_FACE('F1418',(#2069),#73,.F.);
#2071=ORIENTED_EDGE('',*,*,#612,.F.);
#2072=EDGE_CURVE('E607',#603,#1919,#728,.T.);
#2073=ORIENTED_EDGE('',*,*,#2072,.T.);
#2074=ORIENTED_EDGE('',*,*,#2002,.F.);
#2075=EDGE_LOOP('',(#2071,#2073,#2074));
#2076=FACE_BOUND('',#2075,.T.);
#2077=ADVANCED_FACE('F1424',(#2076),#713,.F.);
#2078=ORIENTED_EDGE('',*,*,#2072,.F.);
#2079=ORIENTED_EDGE('',*,*,#1834,.F.);
#2080=ORIENTED_EDGE('',*,*,#2059,.F.);
#2081=EDGE_LOOP('',(#2078,#2079,#2080));
#2082=FACE_BOUND('',#2081,.T.);
#2083=ADVANCED_FACE('F1429',(#2082),#746,.F.);
#2084=EDGE_CURVE('E594',#57,#1940,#801,.T.);
#2085=ORIENTED_EDGE('',*,*,#2084,.F.);
#2086=ORIENTED_EDGE('',*,*,#58,.F.);
#2087=ORIENTED_EDGE('',*,*,#2018,.F.);
#2088=EDGE_LOOP('',(#2085,#2086,#2087));
#2089=FACE_BOUND('',#2088,.T.);
#2090=ADVANCED_FACE('F1492',(#2089),#778,.F.);
#2091=ORIENTED_EDGE('',*,*,#1785,.F.);
#2092=ORIENTED_EDGE('',*,*,#2084,.T.);
#2093=ORIENTED_EDGE('',*,*,#2042,.F.);
#2094=EDGE_LOOP('',(#2091,#2092,#2093));
#2095=FACE_BOUND('',#2094,.T.);
#2096=ADVANCED_FACE('F1501',(#2095),#811,.F.);
#2097=ORIENTED_EDGE('',*,*,#1828,.F.);
#2098=EDGE_CURVE('E1344',#1769,#1965,#866,.T.);
#2099=ORIENTED_EDGE('',*,*,#2098,.T.);
#2100=ORIENTED_EDGE('',*,*,#2065,.F.);
#2101=EDGE_LOOP('',(#2097,#2099,#2100));
#2102=FACE_BOUND('',#2101,.T.);
#2103=ADVANCED_FACE('F1653',(#2102),#876,.F.);
#2104=ORIENTED_EDGE('',*,*,#2098,.F.);
#2105=ORIENTED_EDGE('',*,*,#1791,.F.);
#2106=ORIENTED_EDGE('',*,*,#2036,.F.);
#2107=EDGE_LOOP('',(#2104,#2105,#2106));
#2108=FACE_BOUND('',#2107,.T.);
#2109=ADVANCED_FACE('F1169',(#2108),#843,.F.);
#2110=CARTESIAN_POINT('',(0.,0.,13.97));
#2111=DIRECTION('',(0.,0.,-1.));
#2112=DIRECTION('',(-1.,0.,0.));
#2113=AXIS2_PLACEMENT_3D('',#2110,#2111,#2112);
#2114=CYLINDRICAL_SURFACE('',#2113,6.35);
#2115=ORIENTED_EDGE('',*,*,#1595,.T.);
#2116=ORIENTED_EDGE('',*,*,#1235,.T.);
#2117=ORIENTED_EDGE('',*,*,#1257,.T.);
#2118=EDGE_LOOP('',(#2115,#2116,#2117));
#2119=FACE_BOUND('',#2118,.T.);
#2120=ADVANCED_FACE('F1838',(#2119),#2114,.F.);
#2121=ORIENTED_EDGE('',*,*,#1540,.T.);
#2122=ORIENTED_EDGE('',*,*,#788,.T.);
#2123=ORIENTED_EDGE('',*,*,#819,.T.);
#2124=EDGE_LOOP('',(#2121,#2122,#2123));
#2125=FACE_BOUND('',#2124,.T.);
#2126=ADVANCED_FACE('F1847',(#2125),#2114,.F.);
#2127=ORIENTED_EDGE('',*,*,#1537,.T.);
#2128=ORIENTED_EDGE('',*,*,#33,.T.);
#2129=ORIENTED_EDGE('',*,*,#570,.T.);
#2130=EDGE_LOOP('',(#2127,#2128,#2129));
#2131=FACE_BOUND('',#2130,.T.);
#2132=ADVANCED_FACE('F1856',(#2131),#2114,.F.);
#2133=ORIENTED_EDGE('',*,*,#534,.T.);
#2134=ORIENTED_EDGE('',*,*,#469,.T.);
#2135=ORIENTED_EDGE('',*,*,#1543,.T.);
#2136=EDGE_LOOP('',(#2133,#2134,#2135));
#2137=FACE_BOUND('',#2136,.T.);
#2138=ADVANCED_FACE('F1198',(#2137),#2114,.F.);
#2139=ORIENTED_EDGE('',*,*,#1558,.T.);
#2140=ORIENTED_EDGE('',*,*,#1184,.T.);
#2141=ORIENTED_EDGE('',*,*,#1212,.T.);
#2142=EDGE_LOOP('',(#2139,#2140,#2141));
#2143=FACE_BOUND('',#2142,.T.);
#2144=ADVANCED_FACE('F414',(#2143),#2114,.F.);
#2145=ORIENTED_EDGE('',*,*,#754,.T.);
#2146=ORIENTED_EDGE('',*,*,#723,.T.);
#2147=ORIENTED_EDGE('',*,*,#1552,.T.);
#2148=EDGE_LOOP('',(#2145,#2146,#2147));
#2149=FACE_BOUND('',#2148,.T.);
#2150=ADVANCED_FACE('F1858',(#2149),#2114,.F.);
#2151=ORIENTED_EDGE('',*,*,#693,.T.);
#2152=ORIENTED_EDGE('',*,*,#600,.T.);
#2153=ORIENTED_EDGE('',*,*,#1555,.T.);
#2154=EDGE_LOOP('',(#2151,#2152,#2153));
#2155=FACE_BOUND('',#2154,.T.);
#2156=ADVANCED_FACE('F1889',(#2155),#2114,.F.);
#2157=ORIENTED_EDGE('',*,*,#1549,.T.);
#2158=ORIENTED_EDGE('',*,*,#432,.T.);
#2159=ORIENTED_EDGE('',*,*,#498,.T.);
#2160=EDGE_LOOP('',(#2157,#2158,#2159));
#2161=FACE_BOUND('',#2160,.T.);
#2162=ADVANCED_FACE('F1873',(#2161),#2114,.F.);
#2163=ORIENTED_EDGE('',*,*,#1155,.T.);
#2164=ORIENTED_EDGE('',*,*,#1124,.T.);
#2165=ORIENTED_EDGE('',*,*,#1589,.T.);
#2166=EDGE_LOOP('',(#2163,#2164,#2165));
#2167=FACE_BOUND('',#2166,.T.);
#2168=ADVANCED_FACE('F1881',(#2167),#2114,.F.);
#2169=ORIENTED_EDGE('',*,*,#1025,.T.);
#2170=ORIENTED_EDGE('',*,*,#1003,.T.);
#2171=ORIENTED_EDGE('',*,*,#1583,.T.);
#2172=EDGE_LOOP('',(#2169,#2170,#2171));
#2173=FACE_BOUND('',#2172,.T.);
#2174=ADVANCED_FACE('F1914',(#2173),#2114,.F.);
#2175=ORIENTED_EDGE('',*,*,#402,.T.);
#2176=ORIENTED_EDGE('',*,*,#337,.T.);
#2177=ORIENTED_EDGE('',*,*,#1580,.T.);
#2178=EDGE_LOOP('',(#2175,#2176,#2177));
#2179=FACE_BOUND('',#2178,.T.);
#2180=ADVANCED_FACE('F1242',(#2179),#2114,.F.);
#2181=ORIENTED_EDGE('',*,*,#257,.T.);
#2182=ORIENTED_EDGE('',*,*,#209,.T.);
#2183=ORIENTED_EDGE('',*,*,#1586,.T.);
#2184=EDGE_LOOP('',(#2181,#2182,#2183));
#2185=FACE_BOUND('',#2184,.T.);
#2186=ADVANCED_FACE('F1929',(#2185),#2114,.F.);
#2187=ORIENTED_EDGE('',*,*,#1096,.T.);
#2188=ORIENTED_EDGE('',*,*,#1059,.T.);
#2189=ORIENTED_EDGE('',*,*,#1564,.T.);
#2190=EDGE_LOOP('',(#2187,#2188,#2189));
#2191=FACE_BOUND('',#2190,.T.);
#2192=ADVANCED_FACE('F1380',(#2191),#2114,.F.);
#2193=ORIENTED_EDGE('',*,*,#1570,.T.);
#2194=ORIENTED_EDGE('',*,*,#952,.T.);
#2195=ORIENTED_EDGE('',*,*,#974,.T.);
#2196=EDGE_LOOP('',(#2193,#2194,#2195));
#2197=FACE_BOUND('',#2196,.T.);
#2198=ADVANCED_FACE('F1535',(#2197),#2114,.F.);
#2199=ORIENTED_EDGE('',*,*,#1567,.T.);
#2200=ORIENTED_EDGE('',*,*,#636,.T.);
#2201=ORIENTED_EDGE('',*,*,#670,.T.);
#2202=EDGE_LOOP('',(#2199,#2200,#2201));
#2203=FACE_BOUND('',#2202,.T.);
#2204=ADVANCED_FACE('F1543',(#2203),#2114,.F.);
#2205=ORIENTED_EDGE('',*,*,#1573,.T.);
#2206=ORIENTED_EDGE('',*,*,#292,.T.);
#2207=ORIENTED_EDGE('',*,*,#374,.T.);
#2208=EDGE_LOOP('',(#2205,#2206,#2207));
#2209=FACE_BOUND('',#2208,.T.);
#2210=ADVANCED_FACE('F1930',(#2209),#2114,.F.);
#2211=ORIENTED_EDGE('',*,*,#1577,.T.);
#2212=ORIENTED_EDGE('',*,*,#929,.T.);
#2213=ORIENTED_EDGE('',*,*,#907,.T.);
#2214=EDGE_LOOP('',(#2211,#2212,#2213));
#2215=FACE_BOUND('',#2214,.T.);
#2216=ADVANCED_FACE('F1952',(#2215),#2114,.F.);
#2217=ORIENTED_EDGE('',*,*,#1546,.T.);
#2218=ORIENTED_EDGE('',*,*,#853,.T.);
#2219=ORIENTED_EDGE('',*,*,#884,.T.);
#2220=EDGE_LOOP('',(#2217,#2218,#2219));
#2221=FACE_BOUND('',#2220,.T.);
#2222=ADVANCED_FACE('F1857',(#2221),#2114,.F.);
#2223=ORIENTED_EDGE('',*,*,#1561,.T.);
#2224=ORIENTED_EDGE('',*,*,#120,.T.);
#2225=ORIENTED_EDGE('',*,*,#179,.T.);
#2226=EDGE_LOOP('',(#2223,#2224,#2225));
#2227=FACE_BOUND('',#2226,.T.);
#2228=ADVANCED_FACE('F1389',(#2227),#2114,.F.);
#2229=ORIENTED_EDGE('',*,*,#1592,.T.);
#2230=ORIENTED_EDGE('',*,*,#151,.T.);
#2231=ORIENTED_EDGE('',*,*,#83,.T.);
#2232=EDGE_LOOP('',(#2229,#2230,#2231));
#2233=FACE_BOUND('',#2232,.T.);
#2234=ADVANCED_FACE('F1080',(#2233),#2114,.F.);
#2235=CARTESIAN_POINT('',(0.,0.,26.27));
#2236=DIRECTION('',(0.,0.,-1.));
#2237=DIRECTION('',(-1.,0.,0.));
#2238=AXIS2_PLACEMENT_3D('',#2235,#2236,#2237);
#2239=CONICAL_SURFACE('',#2238,8.8,1.0471975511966);
#2240=ORIENTED_EDGE('',*,*,#1499,.F.);
#2241=EDGE_LOOP('',(#2240));
#2242=FACE_BOUND('',#2241,.T.);
#2243=ORIENTED_EDGE('',*,*,#1432,.F.);
#2244=EDGE_LOOP('',(#2243));
#2245=FACE_BOUND('',#2244,.T.);
#2246=ADVANCED_FACE('F1077',(#2242,#2245),#2239,.T.);
#2247=CARTESIAN_POINT('',(0.,0.,1.96282032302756));
#2248=DIRECTION('',(0.,0.,1.));
#2249=DIRECTION('',(1.,0.,0.));
#2250=AXIS2_PLACEMENT_3D('',#2247,#2248,#2249);
#2251=CONICAL_SURFACE('',#2250,10.,1.0471975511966);
#2252=ORIENTED_EDGE('',*,*,#1527,.F.);
#2253=EDGE_LOOP('',(#2252));
#2254=FACE_BOUND('',#2253,.T.);
#2255=ORIENTED_EDGE('',*,*,#1510,.F.);
#2256=EDGE_LOOP('',(#2255));
#2257=FACE_BOUND('',#2256,.T.);
#2258=ADVANCED_FACE('F17',(#2254,#2257),#2251,.T.);
#2259=CLOSED_SHELL('',(#68,#110,#138,#171,#194,#244,#277,#327,#361,#394,#417,#459,#485,#526,
#557,#590,#626,#662,#685,#708,#741,#773,#806,#838,#871,#897,#921,#942,#966,#993,#1017,#1044,
#1083,#1109,#1142,#1174,#1204,#1225,#1249,#1276,#1293,#1300,#1307,#1314,#1321,#1328,#1335,#1342,
#1349,#1356,#1363,#1370,#1377,#1384,#1391,#1398,#1405,#1412,#1419,#1486,#1514,#1599,#1605,#1636,
#1660,#1684,#1708,#1732,#1749,#1763,#1777,#1795,#1802,#1813,#1820,#1838,#1852,#1863,#1870,#1888,
#1895,#1913,#1927,#1938,#1952,#1963,#1977,#1988,#1995,#2006,#2013,#2024,#2031,#2047,#2054,#2070,
#2077,#2083,#2090,#2096,#2103,#2109,#2120,#2126,#2132,#2138,#2144,#2150,#2156,#2162,#2168,#2174,
#2180,#2186,#2192,#2198,#2204,#2210,#2216,#2222,#2228,#2234,#2246,#2258));
#2260=MANIFOLD_SOLID_BREP('B1',#2259);
#2261=ADVANCED_BREP_SHAPE_REPRESENTATION('',(#18,#2260),#14);
#2262=SHAPE_DEFINITION_REPRESENTATION(#9,#2261);
ENDSEC;
END-ISO-10303-21;
